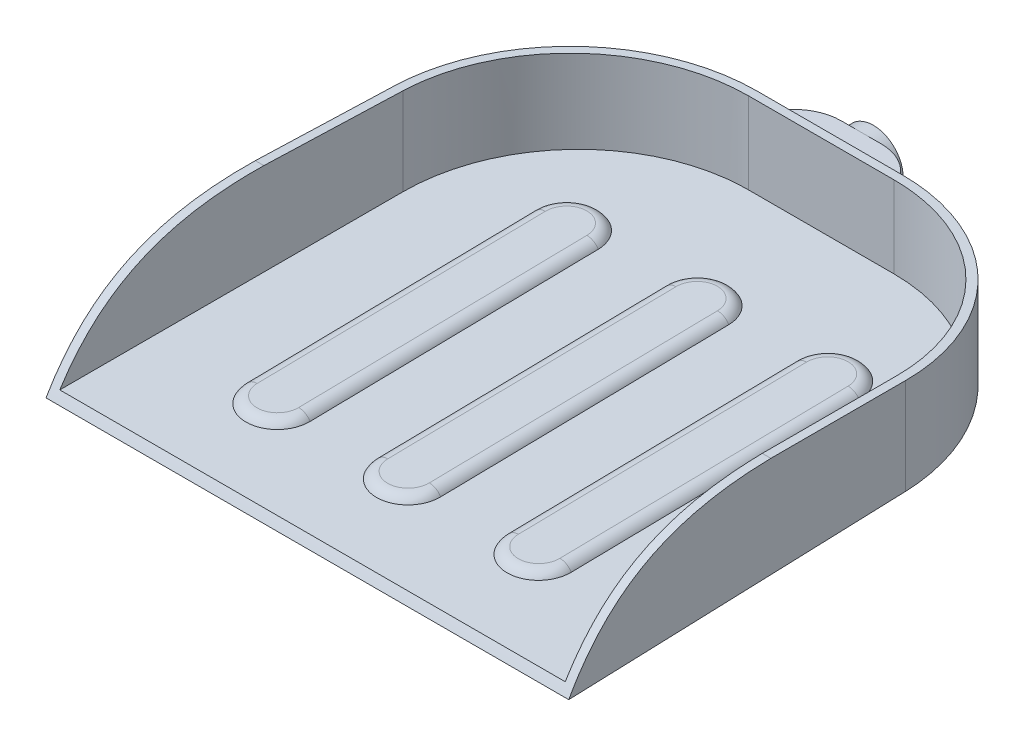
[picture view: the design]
ISO-10303-21;
HEADER;
FILE_DESCRIPTION(('STEP AP214'),'2;1');
FILE_NAME('part.step','',(''),(''),'','','');
FILE_SCHEMA(('AUTOMOTIVE_DESIGN { 1 0 10303 214 1 1 1 1 }'));
ENDSEC;
DATA;
#1=APPLICATION_CONTEXT('core data for automotive mechanical design processes');
#2=APPLICATION_PROTOCOL_DEFINITION('international standard','automotive_design',2000,#1);
#3=PRODUCT_CONTEXT('',#1,'mechanical');
#4=PRODUCT('Part','Part','',(#3));
#5=PRODUCT_RELATED_PRODUCT_CATEGORY('part','',(#4));
#6=PRODUCT_DEFINITION_FORMATION('','',#4);
#7=PRODUCT_DEFINITION_CONTEXT('part definition',#1,'design');
#8=PRODUCT_DEFINITION('design','',#6,#7);
#9=PRODUCT_DEFINITION_SHAPE('','',#8);
#10=(LENGTH_UNIT() NAMED_UNIT(*) SI_UNIT(.MILLI.,.METRE.));
#11=(NAMED_UNIT(*) PLANE_ANGLE_UNIT() SI_UNIT($,.RADIAN.));
#12=(NAMED_UNIT(*) SI_UNIT($,.STERADIAN.) SOLID_ANGLE_UNIT());
#13=UNCERTAINTY_MEASURE_WITH_UNIT(LENGTH_MEASURE(1.E-05),#10,'distance_accuracy_value','');
#14=(GEOMETRIC_REPRESENTATION_CONTEXT(3) GLOBAL_UNCERTAINTY_ASSIGNED_CONTEXT((#13)) GLOBAL_UNIT_ASSIGNED_CONTEXT((#10,
#11,#12)) REPRESENTATION_CONTEXT('',''));
#15=CARTESIAN_POINT('',(0.,0.,0.));
#16=DIRECTION('',(0.,0.,1.));
#17=DIRECTION('',(1.,0.,0.));
#18=AXIS2_PLACEMENT_3D('',#15,#16,#17);
#19=CARTESIAN_POINT('',(-152.5,31.5,-304.8));
#20=DIRECTION('',(0.,0.,-1.));
#21=DIRECTION('',(-1.,0.,0.));
#22=AXIS2_PLACEMENT_3D('',#19,#20,#21);
#23=PLANE('',#22);
#24=DIRECTION('',(1.,0.,0.));
#25=VECTOR('',#24,1.);
#26=CARTESIAN_POINT('',(-152.5,-26.1796962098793,-304.8));
#27=LINE('',#26,#25);
#28=CARTESIAN_POINT('',(-42.3455521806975,-26.1796962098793,-304.8));
#29=VERTEX_POINT('',#28);
#30=CARTESIAN_POINT('',(42.3455521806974,-26.1796962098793,-304.8));
#31=VERTEX_POINT('',#30);
#32=EDGE_CURVE('E772',#29,#31,#27,.T.);
#33=ORIENTED_EDGE('',*,*,#32,.F.);
#34=DIRECTION('',(0.,-1.,0.));
#35=VECTOR('',#34,1.);
#36=CARTESIAN_POINT('',(-42.3455521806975,31.5,-304.8));
#37=LINE('',#36,#35);
#38=CARTESIAN_POINT('',(-42.3455521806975,26.1796962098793,-304.8));
#39=VERTEX_POINT('',#38);
#40=EDGE_CURVE('E760',#29,#39,#37,.F.);
#41=ORIENTED_EDGE('',*,*,#40,.T.);
#42=DIRECTION('',(-1.,0.,0.));
#43=VECTOR('',#42,1.);
#44=CARTESIAN_POINT('',(-152.5,26.1796962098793,-304.8));
#45=LINE('',#44,#43);
#46=CARTESIAN_POINT('',(42.3455521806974,26.1796962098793,-304.8));
#47=VERTEX_POINT('',#46);
#48=EDGE_CURVE('E775',#47,#39,#45,.T.);
#49=ORIENTED_EDGE('',*,*,#48,.F.);
#50=DIRECTION('',(0.,1.,0.));
#51=VECTOR('',#50,1.);
#52=CARTESIAN_POINT('',(42.3455521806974,31.5,-304.8));
#53=LINE('',#52,#51);
#54=EDGE_CURVE('E762',#47,#31,#53,.F.);
#55=ORIENTED_EDGE('',*,*,#54,.T.);
#56=EDGE_LOOP('',(#33,#41,#49,#55));
#57=FACE_BOUND('',#56,.T.);
#58=DIRECTION('',(1.,0.,0.));
#59=VECTOR('',#58,1.);
#60=CARTESIAN_POINT('',(37.8080050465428,-13.1474560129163,-304.8));
#61=LINE('',#60,#59);
#62=CARTESIAN_POINT('',(11.4175479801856,-13.1474560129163,-304.8));
#63=VERTEX_POINT('',#62);
#64=CARTESIAN_POINT('',(37.8080050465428,-13.1474560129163,-304.8));
#65=VERTEX_POINT('',#64);
#66=EDGE_CURVE('E560',#63,#65,#61,.T.);
#67=ORIENTED_EDGE('',*,*,#66,.F.);
#68=CARTESIAN_POINT('',(0.,0.,-304.8));
#69=DIRECTION('',(0.,0.,-1.));
#70=DIRECTION('',(-1.,0.,0.));
#71=AXIS2_PLACEMENT_3D('',#68,#69,#70);
#72=CIRCLE('',#71,17.413098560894);
#73=CARTESIAN_POINT('',(11.4175479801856,13.1474560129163,-304.8));
#74=VERTEX_POINT('',#73);
#75=EDGE_CURVE('E390',#74,#63,#72,.T.);
#76=ORIENTED_EDGE('',*,*,#75,.F.);
#77=DIRECTION('',(-1.,0.,0.));
#78=VECTOR('',#77,1.);
#79=CARTESIAN_POINT('',(37.8080050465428,13.1474560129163,-304.8));
#80=LINE('',#79,#78);
#81=CARTESIAN_POINT('',(37.8080050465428,13.1474560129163,-304.8));
#82=VERTEX_POINT('',#81);
#83=EDGE_CURVE('E408',#82,#74,#80,.T.);
#84=ORIENTED_EDGE('',*,*,#83,.F.);
#85=DIRECTION('',(0.,-1.,0.));
#86=VECTOR('',#85,1.);
#87=CARTESIAN_POINT('',(37.8080050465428,13.1474560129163,-304.8));
#88=LINE('',#87,#86);
#89=CARTESIAN_POINT('',(37.8080050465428,17.413098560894,-304.8));
#90=VERTEX_POINT('',#89);
#91=EDGE_CURVE('E409',#90,#82,#88,.T.);
#92=ORIENTED_EDGE('',*,*,#91,.F.);
#93=DIRECTION('',(1.,0.,0.));
#94=VECTOR('',#93,1.);
#95=CARTESIAN_POINT('',(37.8080050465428,17.413098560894,-304.8));
#96=LINE('',#95,#94);
#97=CARTESIAN_POINT('',(-37.8080050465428,17.413098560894,-304.8));
#98=VERTEX_POINT('',#97);
#99=EDGE_CURVE('E417',#98,#90,#96,.T.);
#100=ORIENTED_EDGE('',*,*,#99,.F.);
#101=DIRECTION('',(0.,1.,0.));
#102=VECTOR('',#101,1.);
#103=CARTESIAN_POINT('',(-37.8080050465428,13.1474560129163,-304.8));
#104=LINE('',#103,#102);
#105=CARTESIAN_POINT('',(-37.8080050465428,13.1474560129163,-304.8));
#106=VERTEX_POINT('',#105);
#107=EDGE_CURVE('E406',#106,#98,#104,.T.);
#108=ORIENTED_EDGE('',*,*,#107,.F.);
#109=CARTESIAN_POINT('',(-11.4175479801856,13.1474560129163,-304.8));
#110=VERTEX_POINT('',#109);
#111=EDGE_CURVE('E396',#110,#106,#80,.T.);
#112=ORIENTED_EDGE('',*,*,#111,.F.);
#113=CARTESIAN_POINT('',(-11.4175479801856,-13.1474560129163,-304.8));
#114=VERTEX_POINT('',#113);
#115=EDGE_CURVE('E377',#114,#110,#72,.T.);
#116=ORIENTED_EDGE('',*,*,#115,.F.);
#117=CARTESIAN_POINT('',(-37.8080050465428,-13.1474560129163,-304.8));
#118=VERTEX_POINT('',#117);
#119=EDGE_CURVE('E557',#118,#114,#61,.T.);
#120=ORIENTED_EDGE('',*,*,#119,.F.);
#121=DIRECTION('',(0.,1.,0.));
#122=VECTOR('',#121,1.);
#123=CARTESIAN_POINT('',(-37.8080050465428,-13.1474560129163,-304.8));
#124=LINE('',#123,#122);
#125=CARTESIAN_POINT('',(-37.8080050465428,-17.413098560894,-304.8));
#126=VERTEX_POINT('',#125);
#127=EDGE_CURVE('E561',#126,#118,#124,.T.);
#128=ORIENTED_EDGE('',*,*,#127,.F.);
#129=DIRECTION('',(-1.,0.,0.));
#130=VECTOR('',#129,1.);
#131=CARTESIAN_POINT('',(37.8080050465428,-17.413098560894,-304.8));
#132=LINE('',#131,#130);
#133=CARTESIAN_POINT('',(37.8080050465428,-17.413098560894,-304.8));
#134=VERTEX_POINT('',#133);
#135=EDGE_CURVE('E564',#134,#126,#132,.T.);
#136=ORIENTED_EDGE('',*,*,#135,.F.);
#137=DIRECTION('',(0.,-1.,0.));
#138=VECTOR('',#137,1.);
#139=CARTESIAN_POINT('',(37.8080050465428,-13.1474560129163,-304.8));
#140=LINE('',#139,#138);
#141=EDGE_CURVE('E400',#65,#134,#140,.T.);
#142=ORIENTED_EDGE('',*,*,#141,.F.);
#143=EDGE_LOOP('',(#67,#76,#84,#92,#100,#108,#112,#116,#120,#128,#136,#142));
#144=FACE_BOUND('',#143,.T.);
#145=ADVANCED_FACE('F31',(#57,#144),#23,.T.);
#146=CARTESIAN_POINT('',(37.8080050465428,13.1474560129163,-323.088));
#147=DIRECTION('',(0.,1.,0.));
#148=DIRECTION('',(0.,0.,1.));
#149=AXIS2_PLACEMENT_3D('',#146,#147,#148);
#150=PLANE('',#149);
#151=ORIENTED_EDGE('',*,*,#111,.T.);
#152=CARTESIAN_POINT('',(-11.5881176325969,13.1474560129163,-295.148));
#153=DIRECTION('',(0.,1.,0.));
#154=DIRECTION('',(0.,0.,1.));
#155=AXIS2_PLACEMENT_3D('',#152,#153,#154);
#156=CIRCLE('',#155,27.94);
#157=CARTESIAN_POINT('',(-11.5881176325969,13.1474560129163,-323.088));
#158=VERTEX_POINT('',#157);
#159=EDGE_CURVE('E641',#106,#158,#156,.F.);
#160=ORIENTED_EDGE('',*,*,#159,.T.);
#161=DIRECTION('',(-1.,0.,0.));
#162=VECTOR('',#161,1.);
#163=CARTESIAN_POINT('',(37.8080050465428,13.1474560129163,-323.088));
#164=LINE('',#163,#162);
#165=CARTESIAN_POINT('',(-11.4175479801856,13.1474560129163,-323.088));
#166=VERTEX_POINT('',#165);
#167=EDGE_CURVE('E399',#166,#158,#164,.T.);
#168=ORIENTED_EDGE('',*,*,#167,.F.);
#169=DIRECTION('',(0.,0.,1.));
#170=VECTOR('',#169,1.);
#171=CARTESIAN_POINT('',(-11.4175479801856,13.1474560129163,-330.2));
#172=LINE('',#171,#170);
#173=EDGE_CURVE('E381',#110,#166,#172,.F.);
#174=ORIENTED_EDGE('',*,*,#173,.F.);
#175=EDGE_LOOP('',(#151,#160,#168,#174));
#176=FACE_BOUND('',#175,.T.);
#177=ADVANCED_FACE('F395',(#176),#150,.F.);
#178=CARTESIAN_POINT('',(11.5881176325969,13.1474560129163,-323.088));
#179=VERTEX_POINT('',#178);
#180=CARTESIAN_POINT('',(11.4175479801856,13.1474560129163,-323.088));
#181=VERTEX_POINT('',#180);
#182=EDGE_CURVE('E554',#179,#181,#164,.T.);
#183=ORIENTED_EDGE('',*,*,#182,.F.);
#184=CARTESIAN_POINT('',(11.5881176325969,13.1474560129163,-295.148));
#185=DIRECTION('',(0.,1.,0.));
#186=DIRECTION('',(0.,0.,1.));
#187=AXIS2_PLACEMENT_3D('',#184,#185,#186);
#188=CIRCLE('',#187,27.94);
#189=EDGE_CURVE('E11',#179,#82,#188,.F.);
#190=ORIENTED_EDGE('',*,*,#189,.T.);
#191=ORIENTED_EDGE('',*,*,#83,.T.);
#192=DIRECTION('',(0.,0.,1.));
#193=VECTOR('',#192,1.);
#194=CARTESIAN_POINT('',(11.4175479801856,13.1474560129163,-330.2));
#195=LINE('',#194,#193);
#196=EDGE_CURVE('E401',#181,#74,#195,.T.);
#197=ORIENTED_EDGE('',*,*,#196,.F.);
#198=EDGE_LOOP('',(#183,#190,#191,#197));
#199=FACE_BOUND('',#198,.T.);
#200=ADVANCED_FACE('F611',(#199),#150,.F.);
#201=CARTESIAN_POINT('',(37.8080050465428,17.413098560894,-323.088));
#202=DIRECTION('',(0.,0.,1.));
#203=DIRECTION('',(1.,0.,0.));
#204=AXIS2_PLACEMENT_3D('',#201,#202,#203);
#205=PLANE('',#204);
#206=ORIENTED_EDGE('',*,*,#167,.T.);
#207=DIRECTION('',(0.,1.,0.));
#208=VECTOR('',#207,1.);
#209=CARTESIAN_POINT('',(-11.5881176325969,17.4130985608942,-323.088));
#210=LINE('',#209,#208);
#211=CARTESIAN_POINT('',(-11.5881176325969,17.413098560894,-323.088));
#212=VERTEX_POINT('',#211);
#213=EDGE_CURVE('E642',#158,#212,#210,.T.);
#214=ORIENTED_EDGE('',*,*,#213,.T.);
#215=DIRECTION('',(1.,0.,0.));
#216=VECTOR('',#215,1.);
#217=CARTESIAN_POINT('',(37.8080050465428,17.413098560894,-323.088));
#218=LINE('',#217,#216);
#219=CARTESIAN_POINT('',(0.,17.413098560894,-323.088));
#220=VERTEX_POINT('',#219);
#221=EDGE_CURVE('E545',#212,#220,#218,.T.);
#222=ORIENTED_EDGE('',*,*,#221,.T.);
#223=CARTESIAN_POINT('',(0.,0.,-323.088));
#224=DIRECTION('',(0.,0.,1.));
#225=DIRECTION('',(1.,0.,0.));
#226=AXIS2_PLACEMENT_3D('',#223,#224,#225);
#227=CIRCLE('',#226,17.413098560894);
#228=EDGE_CURVE('E573',#166,#220,#227,.F.);
#229=ORIENTED_EDGE('',*,*,#228,.F.);
#230=EDGE_LOOP('',(#206,#214,#222,#229));
#231=FACE_BOUND('',#230,.T.);
#232=ADVANCED_FACE('F1174',(#231),#205,.F.);
#233=CARTESIAN_POINT('',(11.5881176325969,17.413098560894,-323.088));
#234=VERTEX_POINT('',#233);
#235=EDGE_CURVE('E550',#220,#234,#218,.T.);
#236=ORIENTED_EDGE('',*,*,#235,.T.);
#237=DIRECTION('',(0.,-1.,0.));
#238=VECTOR('',#237,1.);
#239=CARTESIAN_POINT('',(11.5881176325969,17.413098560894,-323.088));
#240=LINE('',#239,#238);
#241=EDGE_CURVE('E39',#234,#179,#240,.T.);
#242=ORIENTED_EDGE('',*,*,#241,.T.);
#243=ORIENTED_EDGE('',*,*,#182,.T.);
#244=EDGE_CURVE('E574',#220,#181,#227,.F.);
#245=ORIENTED_EDGE('',*,*,#244,.F.);
#246=EDGE_LOOP('',(#236,#242,#243,#245));
#247=FACE_BOUND('',#246,.T.);
#248=ADVANCED_FACE('F1167',(#247),#205,.F.);
#249=CARTESIAN_POINT('',(37.8080050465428,-13.1474560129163,-323.088));
#250=DIRECTION('',(0.,-1.,0.));
#251=DIRECTION('',(0.,0.,-1.));
#252=AXIS2_PLACEMENT_3D('',#249,#250,#251);
#253=PLANE('',#252);
#254=ORIENTED_EDGE('',*,*,#66,.T.);
#255=CARTESIAN_POINT('',(11.5881176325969,-13.1474560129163,-295.148));
#256=DIRECTION('',(0.,-1.,0.));
#257=DIRECTION('',(0.,0.,-1.));
#258=AXIS2_PLACEMENT_3D('',#255,#256,#257);
#259=CIRCLE('',#258,27.94);
#260=CARTESIAN_POINT('',(11.5881176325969,-13.1474560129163,-323.088));
#261=VERTEX_POINT('',#260);
#262=EDGE_CURVE('E649',#65,#261,#259,.F.);
#263=ORIENTED_EDGE('',*,*,#262,.T.);
#264=DIRECTION('',(1.,0.,0.));
#265=VECTOR('',#264,1.);
#266=CARTESIAN_POINT('',(37.8080050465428,-13.1474560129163,-323.088));
#267=LINE('',#266,#265);
#268=CARTESIAN_POINT('',(11.4175479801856,-13.1474560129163,-323.088));
#269=VERTEX_POINT('',#268);
#270=EDGE_CURVE('E569',#269,#261,#267,.T.);
#271=ORIENTED_EDGE('',*,*,#270,.F.);
#272=DIRECTION('',(0.,0.,1.));
#273=VECTOR('',#272,1.);
#274=CARTESIAN_POINT('',(11.4175479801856,-13.1474560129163,-330.2));
#275=LINE('',#274,#273);
#276=EDGE_CURVE('E577',#63,#269,#275,.F.);
#277=ORIENTED_EDGE('',*,*,#276,.F.);
#278=EDGE_LOOP('',(#254,#263,#271,#277));
#279=FACE_BOUND('',#278,.T.);
#280=ADVANCED_FACE('F1159',(#279),#253,.F.);
#281=CARTESIAN_POINT('',(-11.5881176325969,-13.1474560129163,-323.088));
#282=VERTEX_POINT('',#281);
#283=CARTESIAN_POINT('',(-11.4175479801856,-13.1474560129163,-323.088));
#284=VERTEX_POINT('',#283);
#285=EDGE_CURVE('E412',#282,#284,#267,.T.);
#286=ORIENTED_EDGE('',*,*,#285,.F.);
#287=CARTESIAN_POINT('',(-11.5881176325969,-13.1474560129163,-295.148));
#288=DIRECTION('',(0.,-1.,0.));
#289=DIRECTION('',(0.,0.,-1.));
#290=AXIS2_PLACEMENT_3D('',#287,#288,#289);
#291=CIRCLE('',#290,27.94);
#292=EDGE_CURVE('E658',#282,#118,#291,.F.);
#293=ORIENTED_EDGE('',*,*,#292,.T.);
#294=ORIENTED_EDGE('',*,*,#119,.T.);
#295=DIRECTION('',(0.,0.,1.));
#296=VECTOR('',#295,1.);
#297=CARTESIAN_POINT('',(-11.4175479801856,-13.1474560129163,-330.2));
#298=LINE('',#297,#296);
#299=EDGE_CURVE('E385',#284,#114,#298,.T.);
#300=ORIENTED_EDGE('',*,*,#299,.F.);
#301=EDGE_LOOP('',(#286,#293,#294,#300));
#302=FACE_BOUND('',#301,.T.);
#303=ADVANCED_FACE('F1152',(#302),#253,.F.);
#304=CARTESIAN_POINT('',(37.8080050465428,-17.413098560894,-323.088));
#305=DIRECTION('',(0.,0.,-1.));
#306=DIRECTION('',(-1.,0.,0.));
#307=AXIS2_PLACEMENT_3D('',#304,#305,#306);
#308=PLANE('',#307);
#309=DIRECTION('',(-1.,0.,0.));
#310=VECTOR('',#309,1.);
#311=CARTESIAN_POINT('',(37.8080050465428,-17.413098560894,-323.088));
#312=LINE('',#311,#310);
#313=CARTESIAN_POINT('',(0.,-17.413098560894,-323.088));
#314=VERTEX_POINT('',#313);
#315=CARTESIAN_POINT('',(-11.5881176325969,-17.413098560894,-323.088));
#316=VERTEX_POINT('',#315);
#317=EDGE_CURVE('E559',#314,#316,#312,.T.);
#318=ORIENTED_EDGE('',*,*,#317,.T.);
#319=DIRECTION('',(0.,-1.,0.));
#320=VECTOR('',#319,1.);
#321=CARTESIAN_POINT('',(-11.5881176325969,-13.1474560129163,-323.088));
#322=LINE('',#321,#320);
#323=EDGE_CURVE('E660',#316,#282,#322,.F.);
#324=ORIENTED_EDGE('',*,*,#323,.T.);
#325=ORIENTED_EDGE('',*,*,#285,.T.);
#326=CARTESIAN_POINT('',(0.,0.,-323.088));
#327=DIRECTION('',(0.,0.,-1.));
#328=DIRECTION('',(-1.,0.,0.));
#329=AXIS2_PLACEMENT_3D('',#326,#327,#328);
#330=CIRCLE('',#329,17.413098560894);
#331=EDGE_CURVE('E663',#284,#314,#330,.F.);
#332=ORIENTED_EDGE('',*,*,#331,.T.);
#333=EDGE_LOOP('',(#318,#324,#325,#332));
#334=FACE_BOUND('',#333,.T.);
#335=ADVANCED_FACE('F1143',(#334),#308,.T.);
#336=ORIENTED_EDGE('',*,*,#270,.T.);
#337=DIRECTION('',(0.,1.,0.));
#338=VECTOR('',#337,1.);
#339=CARTESIAN_POINT('',(11.5881176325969,-17.413098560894,-323.088));
#340=LINE('',#339,#338);
#341=CARTESIAN_POINT('',(11.5881176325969,-17.413098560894,-323.088));
#342=VERTEX_POINT('',#341);
#343=EDGE_CURVE('E651',#261,#342,#340,.F.);
#344=ORIENTED_EDGE('',*,*,#343,.T.);
#345=EDGE_CURVE('E570',#342,#314,#312,.T.);
#346=ORIENTED_EDGE('',*,*,#345,.T.);
#347=EDGE_CURVE('E664',#314,#269,#330,.F.);
#348=ORIENTED_EDGE('',*,*,#347,.T.);
#349=EDGE_LOOP('',(#336,#344,#346,#348));
#350=FACE_BOUND('',#349,.T.);
#351=ADVANCED_FACE('F809',(#350),#308,.T.);
#352=CARTESIAN_POINT('',(735.33971891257,-31.5,0.));
#353=CARTESIAN_POINT('',(735.33971891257,14.267169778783,-25.904790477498));
#354=CARTESIAN_POINT('',(735.33971891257,29.4048455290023,-65.6087133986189));
#355=CARTESIAN_POINT('',(735.33971891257,29.4048455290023,-120.031319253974));
#356=B_SPLINE_CURVE_WITH_KNOTS('',3,(#352,#353,#354,#355),.UNSPECIFIED.,.F.,.F.,(4,4),(0.,1.),.UNSPECIFIED.);
#357=DIRECTION('',(-1.,0.,0.));
#358=VECTOR('',#357,1.);
#359=SURFACE_OF_LINEAR_EXTRUSION('',#356,#358);
#360=DIRECTION('',(-1.,0.,0.));
#361=VECTOR('',#360,1.);
#362=CARTESIAN_POINT('',(-147.446999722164,-26.4469997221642,-2.99274954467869));
#363=LINE('',#362,#361);
#364=CARTESIAN_POINT('',(-147.446999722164,-26.4469997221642,-2.99274954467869));
#365=VERTEX_POINT('',#364);
#366=CARTESIAN_POINT('',(147.446999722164,-26.4469997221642,-2.9927495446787));
#367=VERTEX_POINT('',#366);
#368=EDGE_CURVE('E451',#365,#367,#363,.F.);
#369=ORIENTED_EDGE('',*,*,#368,.F.);
#370=CARTESIAN_POINT('',(-147.446999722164,-26.4469997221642,-2.99274954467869));
#371=CARTESIAN_POINT('',(-147.437334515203,-25.5536466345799,-3.54646888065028));
#372=CARTESIAN_POINT('',(-147.427496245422,-24.6664141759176,-4.11010297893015));
#373=CARTESIAN_POINT('',(-147.407454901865,-22.9041924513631,-5.25827078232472));
#374=CARTESIAN_POINT('',(-147.397251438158,-22.0292177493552,-5.84282682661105));
#375=CARTESIAN_POINT('',(-147.37647468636,-20.2928506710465,-7.0331261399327));
#376=CARTESIAN_POINT('',(-147.365901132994,-19.4314687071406,-7.63888460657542));
#377=CARTESIAN_POINT('',(-147.344380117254,-17.7236089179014,-8.8718227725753));
#378=CARTESIAN_POINT('',(-147.33343249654,-16.8771376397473,-9.49901154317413));
#379=CARTESIAN_POINT('',(-147.311160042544,-15.2003838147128,-10.774999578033));
#380=CARTESIAN_POINT('',(-147.299835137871,-14.3701043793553,-11.4238029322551));
#381=CARTESIAN_POINT('',(-147.276805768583,-12.7269811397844,-12.743154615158));
#382=CARTESIAN_POINT('',(-147.26510129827,-11.9141375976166,-13.4137032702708));
#383=CARTESIAN_POINT('',(-147.241347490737,-10.3095204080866,-14.7745579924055));
#384=CARTESIAN_POINT('',(-147.229299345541,-9.51768885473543,-15.4647957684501));
#385=CARTESIAN_POINT('',(-147.204825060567,-7.9537396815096,-16.8669266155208));
#386=CARTESIAN_POINT('',(-147.192399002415,-7.18161786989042,-17.5788150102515));
#387=CARTESIAN_POINT('',(-147.167170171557,-5.6581792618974,-19.0241737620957));
#388=CARTESIAN_POINT('',(-147.154367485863,-4.90685773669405,-19.7576391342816));
#389=CARTESIAN_POINT('',(-147.128387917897,-3.42604105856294,-21.2460075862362));
#390=CARTESIAN_POINT('',(-147.115211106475,-2.69654182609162,-22.0009066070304));
#391=CARTESIAN_POINT('',(-147.088487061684,-1.26031417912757,-23.5319261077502));
#392=CARTESIAN_POINT('',(-147.074939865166,-0.553583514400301,-24.3080444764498));
#393=CARTESIAN_POINT('',(-147.047480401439,0.836235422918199,-25.881196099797));
#394=CARTESIAN_POINT('',(-147.033568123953,1.51932302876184,-26.6782299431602));
#395=CARTESIAN_POINT('',(-147.002438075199,3.00137379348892,-28.4616692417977));
#396=CARTESIAN_POINT('',(-146.985137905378,3.79466649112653,-29.4527953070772));
#397=CARTESIAN_POINT('',(-146.950032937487,5.34412875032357,-31.4639575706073));
#398=CARTESIAN_POINT('',(-146.932228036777,6.10029067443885,-32.4839996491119));
#399=CARTESIAN_POINT('',(-146.896138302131,7.57426782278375,-34.5515791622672));
#400=CARTESIAN_POINT('',(-146.877853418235,8.29207903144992,-35.5991194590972));
#401=CARTESIAN_POINT('',(-146.840832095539,9.68840699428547,-37.72006961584));
#402=CARTESIAN_POINT('',(-146.822095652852,10.3669234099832,-38.7934796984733));
#403=CARTESIAN_POINT('',(-146.784202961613,11.6840043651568,-40.9643505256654));
#404=CARTESIAN_POINT('',(-146.76504676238,12.3225735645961,-42.0618084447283));
#405=CARTESIAN_POINT('',(-146.72635983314,13.5590596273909,-44.2781811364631));
#406=CARTESIAN_POINT('',(-146.706829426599,14.1570097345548,-45.3970773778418));
#407=CARTESIAN_POINT('',(-146.667412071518,15.3128331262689,-47.6552961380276));
#408=CARTESIAN_POINT('',(-146.647525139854,15.870708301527,-48.7946176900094));
#409=CARTESIAN_POINT('',(-146.607425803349,16.9467452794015,-51.0919071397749));
#410=CARTESIAN_POINT('',(-146.587213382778,17.4649051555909,-52.2498759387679));
#411=CARTESIAN_POINT('',(-146.546495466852,18.4620765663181,-54.5826037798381));
#412=CARTESIAN_POINT('',(-146.525989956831,18.9410861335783,-55.757363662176));
#413=CARTESIAN_POINT('',(-146.484720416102,19.8606939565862,-58.1216940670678));
#414=CARTESIAN_POINT('',(-146.463956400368,20.3012944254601,-59.3112637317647));
#415=CARTESIAN_POINT('',(-146.408083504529,21.4303329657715,-62.5122197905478));
#416=CARTESIAN_POINT('',(-146.372765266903,22.0849878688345,-64.5356002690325));
#417=CARTESIAN_POINT('',(-146.301609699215,23.2950238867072,-68.6121000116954));
#418=CARTESIAN_POINT('',(-146.265772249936,23.8503817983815,-70.6652261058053));
#419=CARTESIAN_POINT('',(-146.193686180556,24.8683971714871,-74.795034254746));
#420=CARTESIAN_POINT('',(-146.157437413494,25.3310203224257,-76.8717247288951));
#421=CARTESIAN_POINT('',(-146.084639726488,26.1702353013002,-81.0423014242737));
#422=CARTESIAN_POINT('',(-146.04809080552,26.5468268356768,-83.136187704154));
#423=CARTESIAN_POINT('',(-145.974666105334,27.2219880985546,-87.3426859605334));
#424=CARTESIAN_POINT('',(-145.937789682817,27.5203264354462,-89.4553347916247));
#425=CARTESIAN_POINT('',(-145.863892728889,28.0443800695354,-93.6888884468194));
#426=CARTESIAN_POINT('',(-145.82687224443,28.2701173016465,-95.8097905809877));
#427=CARTESIAN_POINT('',(-145.752732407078,28.6556741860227,-100.057259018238));
#428=CARTESIAN_POINT('',(-145.71561306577,28.8155012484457,-102.183824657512));
#429=CARTESIAN_POINT('',(-145.641319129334,29.0754416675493,-106.440121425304));
#430=CARTESIAN_POINT('',(-145.604144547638,29.1755677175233,-108.569851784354));
#431=CARTESIAN_POINT('',(-145.553364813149,29.2754525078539,-111.479020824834));
#432=CARTESIAN_POINT('',(-145.539772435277,29.2985828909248,-112.257727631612));
#433=CARTESIAN_POINT('',(-145.51258585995,29.3378978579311,-113.815245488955));
#434=CARTESIAN_POINT('',(-145.498991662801,29.354083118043,-114.594056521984));
#435=CARTESIAN_POINT('',(-145.471846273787,29.3797253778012,-116.149214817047));
#436=CARTESIAN_POINT('',(-145.458295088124,29.3892044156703,-116.925561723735));
#437=CARTESIAN_POINT('',(-145.431190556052,29.4017640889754,-118.478379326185));
#438=CARTESIAN_POINT('',(-145.417637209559,29.4048441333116,-119.254850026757));
#439=CARTESIAN_POINT('',(-145.404083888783,29.4048455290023,-120.031319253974));
#440=B_SPLINE_CURVE_WITH_KNOTS('',3,(#370,#371,#372,#373,#374,#375,#376,#377,#378,#379,#380,
#381,#382,#383,#384,#385,#386,#387,#388,#389,#390,#391,#392,#393,#394,#395,#396,#397,#398,#399,
#400,#401,#402,#403,#404,#405,#406,#407,#408,#409,#410,#411,#412,#413,#414,#415,#416,#417,#418,
#419,#420,#421,#422,#423,#424,#425,#426,#427,#428,#429,#430,#431,#432,#433,#434,#435,#436,#437,
#438,#439),.UNSPECIFIED.,.F.,.F.,(4,2,2,2,2,2,2,2,2,2,2,2,2,2,2,2,2,2,2,2,2,2,2,2,2,2,2,2,2,2,2,
2,2,2,4),(0.,3.15322192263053,6.3099174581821,9.46892397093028,12.6292846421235,15.790246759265,
18.9512563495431,22.1023876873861,25.252843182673,28.4025764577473,31.5517171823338,
34.7005457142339,37.8494629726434,41.6574401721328,45.4661973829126,49.2753526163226,
53.0845406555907,56.893283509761,60.6988706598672,64.5042781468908,68.3098701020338,
72.1156531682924,75.9212168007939,82.2990957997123,88.6784632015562,95.0601865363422,
101.441931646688,107.842339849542,114.240812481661,120.638565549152,127.03495787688,
129.372445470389,131.709705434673,134.039248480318,136.369006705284),.UNSPECIFIED.);
#441=CARTESIAN_POINT('',(-145.404083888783,29.4048455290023,-120.031319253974));
#442=VERTEX_POINT('',#441);
#443=EDGE_CURVE('E445',#365,#442,#440,.T.);
#444=ORIENTED_EDGE('',*,*,#443,.T.);
#445=DIRECTION('',(-1.,0.,0.));
#446=VECTOR('',#445,1.);
#447=CARTESIAN_POINT('',(735.33971891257,29.4048455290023,-120.031319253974));
#448=LINE('',#447,#446);
#449=CARTESIAN_POINT('',(-150.404845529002,29.4048455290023,-120.031319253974));
#450=VERTEX_POINT('',#449);
#451=EDGE_CURVE('E825',#442,#450,#448,.T.);
#452=ORIENTED_EDGE('',*,*,#451,.T.);
#453=CARTESIAN_POINT('',(-152.5,-31.4999999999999,0.));
#454=CARTESIAN_POINT('',(-152.490668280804,-30.5554742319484,-0.534613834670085));
#455=CARTESIAN_POINT('',(-152.481161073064,-29.6166135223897,-1.0792814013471));
#456=CARTESIAN_POINT('',(-152.461773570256,-27.7500046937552,-2.18999069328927));
#457=CARTESIAN_POINT('',(-152.451892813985,-26.8222723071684,-2.75605884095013));
#458=CARTESIAN_POINT('',(-152.431751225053,-24.979327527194,-3.9099696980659));
#459=CARTESIAN_POINT('',(-152.421490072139,-24.0641266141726,-4.49783075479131));
#460=CARTESIAN_POINT('',(-152.400581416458,-22.2476465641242,-5.69568683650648));
#461=CARTESIAN_POINT('',(-152.389933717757,-21.3463748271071,-6.30569308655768));
#462=CARTESIAN_POINT('',(-152.368246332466,-19.5591259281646,-7.54816255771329));
#463=CARTESIAN_POINT('',(-152.357206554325,-18.673152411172,-8.1806310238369));
#464=CARTESIAN_POINT('',(-152.334730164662,-16.9178448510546,-9.46830252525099));
#465=CARTESIAN_POINT('',(-152.323293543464,-16.0485112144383,-10.1235061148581));
#466=CARTESIAN_POINT('',(-152.300024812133,-14.3281858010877,-11.4565708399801));
#467=CARTESIAN_POINT('',(-152.288192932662,-13.4771837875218,-12.1344187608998));
#468=CARTESIAN_POINT('',(-152.264126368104,-11.7944219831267,-13.5131913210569));
#469=CARTESIAN_POINT('',(-152.251891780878,-10.9626575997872,-14.214110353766));
#470=CARTESIAN_POINT('',(-152.227018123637,-9.31959775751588,-15.6391212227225));
#471=CARTESIAN_POINT('',(-152.214379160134,-8.50829700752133,-16.3632069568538));
#472=CARTESIAN_POINT('',(-152.188696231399,-6.90733200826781,-17.8345809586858));
#473=CARTESIAN_POINT('',(-152.175652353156,-6.11766317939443,-18.5818642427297));
#474=CARTESIAN_POINT('',(-152.149160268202,-4.5610620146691,-20.099594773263));
#475=CARTESIAN_POINT('',(-152.135712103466,-3.79412733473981,-20.8700396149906));
#476=CARTESIAN_POINT('',(-152.108413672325,-2.28403162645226,-22.4339656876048));
#477=CARTESIAN_POINT('',(-152.094563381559,-1.54087204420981,-23.2274483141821));
#478=CARTESIAN_POINT('',(-152.06349561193,0.0751252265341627,-25.0073196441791));
#479=CARTESIAN_POINT('',(-152.046185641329,0.942138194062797,-25.999007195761));
#480=CARTESIAN_POINT('',(-152.010998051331,2.6379725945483,-28.0149028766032));
#481=CARTESIAN_POINT('',(-151.993120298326,3.46678492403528,-29.039118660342));
#482=CARTESIAN_POINT('',(-151.956820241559,5.08451476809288,-31.1187475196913));
#483=CARTESIAN_POINT('',(-151.938397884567,5.87342836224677,-32.1741636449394));
#484=CARTESIAN_POINT('',(-151.90103615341,7.40996384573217,-34.3146157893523));
#485=CARTESIAN_POINT('',(-151.882096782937,8.1575860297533,-35.399651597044));
#486=CARTESIAN_POINT('',(-151.843732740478,9.61047070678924,-37.5975261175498));
#487=CARTESIAN_POINT('',(-151.824308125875,10.3157381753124,-38.7103615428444));
#488=CARTESIAN_POINT('',(-151.785045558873,11.6819176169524,-40.9597124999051));
#489=CARTESIAN_POINT('',(-151.765208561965,12.3429197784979,-42.0961732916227));
#490=CARTESIAN_POINT('',(-151.725116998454,13.621872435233,-44.3930174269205));
#491=CARTESIAN_POINT('',(-151.70486244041,14.2398238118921,-45.5534002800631));
#492=CARTESIAN_POINT('',(-151.663970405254,15.4327622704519,-47.8961034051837));
#493=CARTESIAN_POINT('',(-151.643332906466,16.0077469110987,-49.0784249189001));
#494=CARTESIAN_POINT('',(-151.601711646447,17.1151048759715,-51.4629053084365));
#495=CARTESIAN_POINT('',(-151.580727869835,17.6474763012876,-52.665065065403));
#496=CARTESIAN_POINT('',(-151.538453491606,18.6701937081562,-55.0869625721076));
#497=CARTESIAN_POINT('',(-151.517162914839,19.160543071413,-56.3066988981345));
#498=CARTESIAN_POINT('',(-151.462582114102,20.357282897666,-59.4336308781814));
#499=CARTESIAN_POINT('',(-151.429099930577,21.0350879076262,-61.3518238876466));
#500=CARTESIAN_POINT('',(-151.361598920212,22.2968934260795,-65.218954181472));
#501=CARTESIAN_POINT('',(-151.327580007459,22.8808787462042,-67.1678963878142));
#502=CARTESIAN_POINT('',(-151.259108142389,23.9604734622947,-71.0906469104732));
#503=CARTESIAN_POINT('',(-151.224655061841,24.4560560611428,-73.0644625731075));
#504=CARTESIAN_POINT('',(-151.155420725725,25.3645012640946,-77.0308950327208));
#505=CARTESIAN_POINT('',(-151.120639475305,25.7773651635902,-79.0235115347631));
#506=CARTESIAN_POINT('',(-151.050688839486,26.5280057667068,-83.0309807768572));
#507=CARTESIAN_POINT('',(-151.015518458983,26.8654761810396,-85.0458905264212));
#508=CARTESIAN_POINT('',(-150.945002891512,27.4693377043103,-89.0857246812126));
#509=CARTESIAN_POINT('',(-150.909657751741,27.7357470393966,-91.1106463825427));
#510=CARTESIAN_POINT('',(-150.838840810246,28.2035942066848,-95.1677462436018));
#511=CARTESIAN_POINT('',(-150.803369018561,28.405037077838,-97.1999238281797));
#512=CARTESIAN_POINT('',(-150.732345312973,28.7486729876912,-101.268869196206));
#513=CARTESIAN_POINT('',(-150.696793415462,28.8908772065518,-103.305636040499));
#514=CARTESIAN_POINT('',(-150.646948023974,29.0523884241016,-106.161276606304));
#515=CARTESIAN_POINT('',(-150.632675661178,29.0942903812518,-106.978939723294));
#516=CARTESIAN_POINT('',(-150.604126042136,29.1697537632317,-108.614546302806));
#517=CARTESIAN_POINT('',(-150.589848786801,29.2033163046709,-109.432489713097));
#518=CARTESIAN_POINT('',(-150.561290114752,29.2624249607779,-111.068614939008));
#519=CARTESIAN_POINT('',(-150.547008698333,29.2879715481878,-111.886796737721));
#520=CARTESIAN_POINT('',(-150.518521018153,29.3312388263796,-113.518854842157));
#521=CARTESIAN_POINT('',(-150.504314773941,29.3490018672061,-114.332730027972));
#522=CARTESIAN_POINT('',(-150.475899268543,29.3772003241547,-115.960653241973));
#523=CARTESIAN_POINT('',(-150.461690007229,29.3876353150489,-116.774701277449));
#524=CARTESIAN_POINT('',(-150.433268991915,29.4014573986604,-118.402940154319));
#525=CARTESIAN_POINT('',(-150.419057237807,29.4048437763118,-119.217131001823));
#526=CARTESIAN_POINT('',(-150.404845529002,29.4048455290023,-120.031319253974));
#527=B_SPLINE_CURVE_WITH_KNOTS('',3,(#453,#454,#455,#456,#457,#458,#459,#460,#461,#462,#463,
#464,#465,#466,#467,#468,#469,#470,#471,#472,#473,#474,#475,#476,#477,#478,#479,#480,#481,#482,
#483,#484,#485,#486,#487,#488,#489,#490,#491,#492,#493,#494,#495,#496,#497,#498,#499,#500,#501,
#502,#503,#504,#505,#506,#507,#508,#509,#510,#511,#512,#513,#514,#515,#516,#517,#518,#519,#520,
#521,#522,#523,#524,#525,#526),.UNSPECIFIED.,.F.,.F.,(4,2,2,2,2,2,2,2,2,2,2,2,2,2,2,2,2,2,2,2,2,
2,2,2,2,2,2,2,2,2,2,2,2,2,2,2,4),(0.,3.2560836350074,6.51632786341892,9.77938214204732,
13.0441141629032,16.3096135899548,19.5751926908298,22.8388982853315,26.1018165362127,
29.3638822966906,32.625252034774,35.886284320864,39.147514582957,43.0986440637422,
47.0507103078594,51.0031641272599,54.955589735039,58.9075501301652,62.8511968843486,
66.7947628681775,70.7385527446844,74.6825182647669,78.6261660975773,84.7275183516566,
90.829857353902,96.9340429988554,103.038133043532,109.166587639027,115.293468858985,
121.419874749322,127.545123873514,130.00167655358,132.457900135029,134.913978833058,
137.356522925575,139.799208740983,142.242142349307),.UNSPECIFIED.);
#528=CARTESIAN_POINT('',(-152.5,-31.5,0.));
#529=VERTEX_POINT('',#528);
#530=EDGE_CURVE('E789',#529,#450,#527,.T.);
#531=ORIENTED_EDGE('',*,*,#530,.F.);
#532=DIRECTION('',(1.,0.,0.));
#533=VECTOR('',#532,1.);
#534=CARTESIAN_POINT('',(-152.5,-31.5,0.));
#535=LINE('',#534,#533);
#536=CARTESIAN_POINT('',(152.5,-31.5,0.));
#537=VERTEX_POINT('',#536);
#538=EDGE_CURVE('E776',#529,#537,#535,.T.);
#539=ORIENTED_EDGE('',*,*,#538,.T.);
#540=CARTESIAN_POINT('',(150.404845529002,29.4048455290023,-120.031319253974));
#541=CARTESIAN_POINT('',(150.431344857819,29.4048240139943,-118.513173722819));
#542=CARTESIAN_POINT('',(150.457844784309,29.393064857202,-116.994993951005));
#543=CARTESIAN_POINT('',(150.510910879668,29.34411134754,-113.954839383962));
#544=CARTESIAN_POINT('',(150.537477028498,29.3068465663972,-112.432865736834));
#545=CARTESIAN_POINT('',(150.590646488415,29.2047992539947,-109.386789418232));
#546=CARTESIAN_POINT('',(150.617249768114,29.1399620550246,-107.862688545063));
#547=CARTESIAN_POINT('',(150.670463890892,28.9805842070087,-104.814053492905));
#548=CARTESIAN_POINT('',(150.697074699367,28.8860053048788,-103.289521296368));
#549=CARTESIAN_POINT('',(150.750274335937,28.6648983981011,-100.241716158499));
#550=CARTESIAN_POINT('',(150.776863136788,28.5383487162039,-98.718444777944));
#551=CARTESIAN_POINT('',(150.829989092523,28.2509870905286,-95.6748608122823));
#552=CARTESIAN_POINT('',(150.856526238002,28.0901694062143,-94.1545487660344));
#553=CARTESIAN_POINT('',(150.909992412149,27.7286989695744,-91.0914737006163));
#554=CARTESIAN_POINT('',(150.936920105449,27.5273941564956,-89.5487871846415));
#555=CARTESIAN_POINT('',(150.990660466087,27.084260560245,-86.4700039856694));
#556=CARTESIAN_POINT('',(151.017473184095,26.8424520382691,-84.9339043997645));
#557=CARTESIAN_POINT('',(151.070952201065,26.3156927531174,-81.8700935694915));
#558=CARTESIAN_POINT('',(151.097618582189,26.0307694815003,-80.3423776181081));
#559=CARTESIAN_POINT('',(151.150773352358,25.4151202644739,-77.2971428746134));
#560=CARTESIAN_POINT('',(151.177261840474,25.0844224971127,-75.7796184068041));
#561=CARTESIAN_POINT('',(151.230029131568,24.3745333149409,-72.7565823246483));
#562=CARTESIAN_POINT('',(151.256308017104,23.9953621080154,-71.2510659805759));
#563=CARTESIAN_POINT('',(151.308624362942,23.1858177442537,-68.2538645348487));
#564=CARTESIAN_POINT('',(151.334661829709,22.7554459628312,-66.7621790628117));
#565=CARTESIAN_POINT('',(151.386284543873,21.8439527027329,-63.8047157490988));
#566=CARTESIAN_POINT('',(151.411871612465,21.3631706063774,-62.3388335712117));
#567=CARTESIAN_POINT('',(151.46271501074,20.3464057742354,-59.4260172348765));
#568=CARTESIAN_POINT('',(151.487971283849,19.8104137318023,-57.9790863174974));
#569=CARTESIAN_POINT('',(151.538093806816,18.6815037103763,-55.1075688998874));
#570=CARTESIAN_POINT('',(151.562960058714,18.0885860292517,-53.6829822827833));
#571=CARTESIAN_POINT('',(151.612245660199,16.8444533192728,-50.8594120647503));
#572=CARTESIAN_POINT('',(151.636664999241,16.1932369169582,-49.460429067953));
#573=CARTESIAN_POINT('',(151.684827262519,14.836478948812,-46.7012148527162));
#574=CARTESIAN_POINT('',(151.708573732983,14.1313510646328,-45.340780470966));
#575=CARTESIAN_POINT('',(151.755511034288,12.6625448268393,-42.651744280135));
#576=CARTESIAN_POINT('',(151.778701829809,11.8988627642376,-41.3231444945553));
#577=CARTESIAN_POINT('',(151.824469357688,10.3134419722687,-38.7011245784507));
#578=CARTESIAN_POINT('',(151.847046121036,9.49170618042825,-37.4077026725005));
#579=CARTESIAN_POINT('',(151.891534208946,7.79122234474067,-34.8589818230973));
#580=CARTESIAN_POINT('',(151.913445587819,6.9124789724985,-33.6036797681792));
#581=CARTESIAN_POINT('',(151.949426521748,5.39952589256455,-31.5423334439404));
#582=CARTESIAN_POINT('',(151.963692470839,4.78058155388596,-30.7250377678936));
#583=CARTESIAN_POINT('',(151.991895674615,3.51851186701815,-29.1092773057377));
#584=CARTESIAN_POINT('',(152.005832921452,2.8753859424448,-28.3108129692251));
#585=CARTESIAN_POINT('',(152.033368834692,1.56566828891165,-26.7332815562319));
#586=CARTESIAN_POINT('',(152.046967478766,0.899075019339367,-25.9542157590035));
#587=CARTESIAN_POINT('',(152.073817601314,-0.456747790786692,-24.4159732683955));
#588=CARTESIAN_POINT('',(152.087069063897,-1.14597836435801,-23.656797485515));
#589=CARTESIAN_POINT('',(152.113217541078,-2.54614869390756,-22.1587522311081));
#590=CARTESIAN_POINT('',(152.12611456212,-3.25708805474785,-21.4198823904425));
#591=CARTESIAN_POINT('',(152.151550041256,-4.69974230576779,-19.9626847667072));
#592=CARTESIAN_POINT('',(152.164088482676,-5.43145815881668,-19.2443579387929));
#593=CARTESIAN_POINT('',(152.201239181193,-7.66098686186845,-17.1159958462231));
#594=CARTESIAN_POINT('',(152.225306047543,-9.18884729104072,-15.7372059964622));
#595=CARTESIAN_POINT('',(152.271977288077,-12.3157189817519,-13.0634124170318));
#596=CARTESIAN_POINT('',(152.294581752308,-13.9147258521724,-11.7684035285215));
#597=CARTESIAN_POINT('',(152.338350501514,-17.1754730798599,-9.2608935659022));
#598=CARTESIAN_POINT('',(152.359515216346,-18.837194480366,-8.04836786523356));
#599=CARTESIAN_POINT('',(152.387164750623,-21.1191012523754,-6.46432710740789));
#600=CARTESIAN_POINT('',(152.394261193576,-21.7152350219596,-6.05777216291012));
#601=CARTESIAN_POINT('',(152.408284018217,-22.9138726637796,-5.25440507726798));
#602=CARTESIAN_POINT('',(152.415210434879,-23.5163751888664,-4.85759093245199));
#603=CARTESIAN_POINT('',(152.428896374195,-24.727487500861,-4.07352399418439));
#604=CARTESIAN_POINT('',(152.43565591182,-25.3360967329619,-3.68627034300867));
#605=CARTESIAN_POINT('',(152.448979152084,-26.556218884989,-2.9229824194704));
#606=CARTESIAN_POINT('',(152.455543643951,-27.167703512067,-2.54690293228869));
#607=CARTESIAN_POINT('',(152.468513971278,-28.3962419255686,-1.80383337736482));
#608=CARTESIAN_POINT('',(152.474919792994,-29.013296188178,-1.43684409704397));
#609=CARTESIAN_POINT('',(152.487576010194,-30.2527382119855,-0.711769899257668));
#610=CARTESIAN_POINT('',(152.493826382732,-30.8751267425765,-0.353686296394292));
#611=CARTESIAN_POINT('',(152.5,-31.5,0.));
#612=B_SPLINE_CURVE_WITH_KNOTS('',3,(#540,#541,#542,#543,#544,#545,#546,#547,#548,#549,#550,
#551,#552,#553,#554,#555,#556,#557,#558,#559,#560,#561,#562,#563,#564,#565,#566,#567,#568,#569,
#570,#571,#572,#573,#574,#575,#576,#577,#578,#579,#580,#581,#582,#583,#584,#585,#586,#587,#588,
#589,#590,#591,#592,#593,#594,#595,#596,#597,#598,#599,#600,#601,#602,#603,#604,#605,#606,#607,
#608,#609,#610,#611),.UNSPECIFIED.,.F.,.F.,(4,2,2,2,2,2,2,2,2,2,2,2,2,2,2,2,2,2,2,2,2,2,2,2,2,2,
2,2,2,2,2,2,2,2,2,4),(0.,4.55513608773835,9.12290121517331,13.6997653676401,18.2825404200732,
22.8684311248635,27.4550906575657,32.1225798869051,36.7877412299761,41.4499403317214,
46.1092821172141,50.7666877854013,55.4239683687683,60.0516944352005,64.6802018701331,
69.3086850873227,73.9372773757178,78.5333604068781,83.1297348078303,87.7258767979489,
92.3216426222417,95.397164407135,98.4727595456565,101.548556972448,104.624494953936,
107.700376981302,110.776401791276,116.947444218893,123.118106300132,129.286917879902,
131.451674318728,133.61598167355,135.780094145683,137.933736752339,140.087565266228,
142.241709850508),.UNSPECIFIED.);
#613=CARTESIAN_POINT('',(150.404845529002,29.4048455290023,-120.031319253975));
#614=VERTEX_POINT('',#613);
#615=EDGE_CURVE('E795',#614,#537,#612,.T.);
#616=ORIENTED_EDGE('',*,*,#615,.F.);
#617=CARTESIAN_POINT('',(145.404083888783,29.4048455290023,-120.031319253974));
#618=VERTEX_POINT('',#617);
#619=EDGE_CURVE('E820',#614,#618,#448,.T.);
#620=ORIENTED_EDGE('',*,*,#619,.T.);
#621=CARTESIAN_POINT('',(147.460544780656,-27.7135913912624,-2.21675366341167));
#622=CARTESIAN_POINT('',(147.449112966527,-26.6321186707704,-2.87168185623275));
#623=CARTESIAN_POINT('',(147.437433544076,-25.5591843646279,-3.54079552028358));
#624=CARTESIAN_POINT('',(147.413544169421,-23.4301322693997,-4.90941687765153));
#625=CARTESIAN_POINT('',(147.401333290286,-22.3740486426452,-5.6089776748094));
#626=CARTESIAN_POINT('',(147.376372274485,-20.2811349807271,-7.03899331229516));
#627=CARTESIAN_POINT('',(147.363621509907,-19.2443295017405,-7.76948412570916));
#628=CARTESIAN_POINT('',(147.337574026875,-17.1923694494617,-9.2617434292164));
#629=CARTESIAN_POINT('',(147.324276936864,-16.1772303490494,-10.023533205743));
#630=CARTESIAN_POINT('',(147.297131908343,-14.1709157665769,-11.5786708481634));
#631=CARTESIAN_POINT('',(147.283283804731,-13.1797476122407,-12.3720281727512));
#632=CARTESIAN_POINT('',(147.255034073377,-11.2235990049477,-13.9904541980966));
#633=CARTESIAN_POINT('',(147.240632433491,-10.2586191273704,-14.8155235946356));
#634=CARTESIAN_POINT('',(147.211394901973,-8.36470427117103,-16.4905406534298));
#635=CARTESIAN_POINT('',(147.196563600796,-7.43553677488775,-17.3402253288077));
#636=CARTESIAN_POINT('',(147.166360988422,-5.60713393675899,-19.0705318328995));
#637=CARTESIAN_POINT('',(147.15098988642,-4.70788725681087,-19.9511416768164));
#638=CARTESIAN_POINT('',(147.119713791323,-2.94115386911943,-21.7429479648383));
#639=CARTESIAN_POINT('',(147.103809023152,-2.07365409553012,-22.6541315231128));
#640=CARTESIAN_POINT('',(147.071474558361,-0.372066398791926,-24.506571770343));
#641=CARTESIAN_POINT('',(147.05504505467,0.462033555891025,-25.4478174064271));
#642=CARTESIAN_POINT('',(147.021673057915,2.0953578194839,-27.3596978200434));
#643=CARTESIAN_POINT('',(147.00473069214,2.89459066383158,-28.3303253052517));
#644=CARTESIAN_POINT('',(146.970348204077,4.45691014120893,-30.3000967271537));
#645=CARTESIAN_POINT('',(146.952908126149,5.21999997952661,-31.2992381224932));
#646=CARTESIAN_POINT('',(146.916110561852,6.7695239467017,-33.4073691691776));
#647=CARTESIAN_POINT('',(146.896712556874,7.5528019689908,-34.5186801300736));
#648=CARTESIAN_POINT('',(146.857384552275,9.07475656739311,-36.7717800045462));
#649=CARTESIAN_POINT('',(146.837454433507,9.81342303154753,-37.9135757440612));
#650=CARTESIAN_POINT('',(146.797098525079,11.2452661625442,-40.2255641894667));
#651=CARTESIAN_POINT('',(146.776672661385,11.9384359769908,-41.3957611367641));
#652=CARTESIAN_POINT('',(146.735365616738,13.2787684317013,-43.7622401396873));
#653=CARTESIAN_POINT('',(146.714484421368,13.9259296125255,-44.9585230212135));
#654=CARTESIAN_POINT('',(146.672310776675,15.1740924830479,-47.3746495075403));
#655=CARTESIAN_POINT('',(146.651018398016,15.7751020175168,-48.5944890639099));
#656=CARTESIAN_POINT('',(146.608090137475,16.9306120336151,-51.0538474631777));
#657=CARTESIAN_POINT('',(146.586454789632,17.4851777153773,-52.2933357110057));
#658=CARTESIAN_POINT('',(146.542853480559,18.5493928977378,-54.7912530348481));
#659=CARTESIAN_POINT('',(146.520887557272,19.0590475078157,-56.0496799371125));
#660=CARTESIAN_POINT('',(146.476660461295,20.0345347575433,-58.5834485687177));
#661=CARTESIAN_POINT('',(146.4543992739,20.5003652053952,-59.8587911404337));
#662=CARTESIAN_POINT('',(146.409617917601,21.3894652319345,-62.4243133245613));
#663=CARTESIAN_POINT('',(146.387097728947,21.8127315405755,-63.7144940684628));
#664=CARTESIAN_POINT('',(146.341835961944,22.6181016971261,-66.3075389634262));
#665=CARTESIAN_POINT('',(146.319094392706,23.0002072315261,-67.6104025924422));
#666=CARTESIAN_POINT('',(146.264453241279,23.867171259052,-70.7407920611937));
#667=CARTESIAN_POINT('',(146.232463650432,24.33347116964,-72.5734744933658));
#668=CARTESIAN_POINT('',(146.168188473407,25.1941441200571,-76.2557969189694));
#669=CARTESIAN_POINT('',(146.13590284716,25.588507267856,-78.1054392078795));
#670=CARTESIAN_POINT('',(146.071106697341,26.3101266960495,-81.8176081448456));
#671=CARTESIAN_POINT('',(146.038596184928,26.637386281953,-83.6801341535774));
#672=CARTESIAN_POINT('',(145.973405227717,27.2297363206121,-87.4149215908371));
#673=CARTESIAN_POINT('',(145.940724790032,27.4948293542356,-89.2871826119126));
#674=CARTESIAN_POINT('',(145.886035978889,27.8897168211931,-92.4203025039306));
#675=CARTESIAN_POINT('',(145.864061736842,28.0353020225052,-93.6792059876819));
#676=CARTESIAN_POINT('',(145.820068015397,28.3021199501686,-96.1996046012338));
#677=CARTESIAN_POINT('',(145.798048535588,28.4233524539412,-97.4610997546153));
#678=CARTESIAN_POINT('',(145.753974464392,28.6428229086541,-99.9861016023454));
#679=CARTESIAN_POINT('',(145.731919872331,28.741060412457,-101.249608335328));
#680=CARTESIAN_POINT('',(145.687784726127,28.9158440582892,-103.778109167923));
#681=CARTESIAN_POINT('',(145.665704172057,28.9923902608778,-105.043103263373));
#682=CARTESIAN_POINT('',(145.621524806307,29.125041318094,-107.574137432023));
#683=CARTESIAN_POINT('',(145.599425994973,29.1811465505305,-108.840177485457));
#684=CARTESIAN_POINT('',(145.566269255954,29.2508664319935,-110.739725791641));
#685=CARTESIAN_POINT('',(145.555215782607,29.2716998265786,-111.372978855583));
#686=CARTESIAN_POINT('',(145.533106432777,29.3086976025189,-112.639622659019));
#687=CARTESIAN_POINT('',(145.522050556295,29.3248619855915,-113.273013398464));
#688=CARTESIAN_POINT('',(145.502766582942,29.3491046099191,-114.377791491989));
#689=CARTESIAN_POINT('',(145.494538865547,29.3581935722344,-114.849157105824));
#690=CARTESIAN_POINT('',(145.478082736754,29.3739199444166,-115.791928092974));
#691=CARTESIAN_POINT('',(145.469854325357,29.3805573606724,-116.263333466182));
#692=CARTESIAN_POINT('',(145.453397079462,29.3914363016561,-117.206168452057));
#693=CARTESIAN_POINT('',(145.445168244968,29.3956778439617,-117.67759806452));
#694=CARTESIAN_POINT('',(145.432824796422,29.4002825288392,-118.384753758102));
#695=CARTESIAN_POINT('',(145.428710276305,29.4015244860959,-118.62047445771));
#696=CARTESIAN_POINT('',(145.420481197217,29.4034313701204,-119.091918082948));
#697=CARTESIAN_POINT('',(145.416366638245,29.4040962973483,-119.327641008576));
#698=CARTESIAN_POINT('',(145.410194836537,29.4046591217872,-119.681223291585));
#699=CARTESIAN_POINT('',(145.408137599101,29.4047743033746,-119.799082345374));
#700=CARTESIAN_POINT('',(145.404023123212,29.4048721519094,-120.034800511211));
#701=CARTESIAN_POINT('',(145.401965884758,29.4048548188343,-120.152659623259));
#702=CARTESIAN_POINT('',(145.395794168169,29.4048269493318,-120.50623702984));
#703=CARTESIAN_POINT('',(145.39167969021,29.4048405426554,-120.741955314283));
#704=CARTESIAN_POINT('',(145.383450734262,29.404850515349,-121.21339188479));
#705=CARTESIAN_POINT('',(145.379336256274,29.4048468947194,-121.449110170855));
#706=CARTESIAN_POINT('',(145.37110730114,29.4048441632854,-121.92054669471));
#707=CARTESIAN_POINT('',(145.366992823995,29.40484505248,-122.156264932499));
#708=CARTESIAN_POINT('',(145.354649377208,29.4048464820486,-122.863420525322));
#709=CARTESIAN_POINT('',(145.346420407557,29.4048457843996,-123.334857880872));
#710=CARTESIAN_POINT('',(145.329962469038,29.4048452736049,-124.277732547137));
#711=CARTESIAN_POINT('',(145.32173350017,29.4048454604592,-124.749169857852));
#712=CARTESIAN_POINT('',(145.305275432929,29.4048455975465,-125.69205189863));
#713=CARTESIAN_POINT('',(145.297046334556,29.4048455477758,-126.163496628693));
#714=CARTESIAN_POINT('',(145.280588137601,29.4048455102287,-127.106386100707));
#715=CARTESIAN_POINT('',(145.272359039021,29.4048455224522,-127.577830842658));
#716=CARTESIAN_POINT('',(145.247671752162,29.4048455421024,-128.992164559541));
#717=CARTESIAN_POINT('',(145.231213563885,29.404845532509,-129.935053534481));
#718=CARTESIAN_POINT('',(145.198297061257,29.4048455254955,-131.820838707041));
#719=CARTESIAN_POINT('',(145.181838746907,29.4048455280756,-132.763734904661));
#720=CARTESIAN_POINT('',(145.148922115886,29.404845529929,-134.649527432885));
#721=CARTESIAN_POINT('',(145.132463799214,29.4048455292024,-135.592423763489));
#722=CARTESIAN_POINT('',(145.105177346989,29.4048455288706,-137.1556635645));
#723=CARTESIAN_POINT('',(145.094349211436,29.4048455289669,-137.776007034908));
#724=CARTESIAN_POINT('',(145.072692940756,29.4048455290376,-139.016693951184));
#725=CARTESIAN_POINT('',(145.061864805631,29.4048455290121,-139.637037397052));
#726=CARTESIAN_POINT('',(145.040208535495,29.4048455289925,-140.877724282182));
#727=CARTESIAN_POINT('',(145.029380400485,29.4048455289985,-141.498067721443));
#728=CARTESIAN_POINT('',(144.986068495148,29.4048455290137,-143.97940511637));
#729=CARTESIAN_POINT('',(144.953584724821,29.4048455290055,-145.840399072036));
#730=CARTESIAN_POINT('',(144.888618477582,29.404845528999,-149.562312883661));
#731=CARTESIAN_POINT('',(144.85613600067,29.4048455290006,-151.423232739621));
#732=CARTESIAN_POINT('',(144.791172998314,29.4048455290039,-155.144960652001));
#733=CARTESIAN_POINT('',(144.75869247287,29.4048455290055,-157.005768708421));
#734=CARTESIAN_POINT('',(144.726211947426,29.4048455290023,-158.866576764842));
#735=B_SPLINE_CURVE_WITH_KNOTS('',3,(#621,#622,#623,#624,#625,#626,#627,#628,#629,#630,#631,
#632,#633,#634,#635,#636,#637,#638,#639,#640,#641,#642,#643,#644,#645,#646,#647,#648,#649,#650,
#651,#652,#653,#654,#655,#656,#657,#658,#659,#660,#661,#662,#663,#664,#665,#666,#667,#668,#669,
#670,#671,#672,#673,#674,#675,#676,#677,#678,#679,#680,#681,#682,#683,#684,#685,#686,#687,#688,
#689,#690,#691,#692,#693,#694,#695,#696,#697,#698,#699,#700,#701,#702,#703,#704,#705,#706,#707,
#708,#709,#710,#711,#712,#713,#714,#715,#716,#717,#718,#719,#720,#721,#722,#723,#724,#725,#726,
#727,#728,#729,#730,#731,#732,#733,#734),.UNSPECIFIED.,.F.,.F.,(4,2,2,2,2,2,2,2,2,2,2,2,2,2,2,2,
2,2,2,2,2,2,2,2,2,2,2,2,2,2,2,2,2,2,2,2,2,2,2,2,2,2,2,2,2,2,2,2,2,2,2,2,2,2,2,2,4),(0.,
3.79308702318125,7.59307788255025,11.3976167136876,15.204787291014,19.0131073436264,
22.8215110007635,26.598338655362,30.373718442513,34.1475265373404,37.919962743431,
41.6914702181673,45.4626425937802,49.5407932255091,53.6198647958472,57.6995493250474,
61.7793632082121,65.8584820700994,69.9317749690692,74.0046038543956,78.0776363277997,
82.1509814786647,86.2241596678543,91.8965429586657,97.5697056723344,103.242588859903,
108.915236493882,112.71746665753,116.51973157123,120.322070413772,124.124398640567,
127.926656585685,129.82771908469,131.728780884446,133.143350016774,134.557915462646,
135.972470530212,136.679749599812,137.387028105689,137.740659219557,138.094290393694,
138.801552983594,139.508815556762,140.216077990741,141.630605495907,143.045132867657,
144.459682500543,145.874232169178,148.703329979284,151.532449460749,154.36156934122,
156.222883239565,158.084197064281,159.945510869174,165.529343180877,171.1129531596,
176.696227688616),.UNSPECIFIED.);
#736=EDGE_CURVE('E438',#618,#367,#735,.F.);
#737=ORIENTED_EDGE('',*,*,#736,.T.);
#738=EDGE_LOOP('',(#369,#444,#452,#531,#539,#616,#620,#737));
#739=FACE_BOUND('',#738,.T.);
#740=ADVANCED_FACE('F804',(#739),#359,.T.);
#741=CARTESIAN_POINT('',(-152.5,-31.5,0.));
#742=DIRECTION('',(-0.999847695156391,0.,-0.0174524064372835));
#743=DIRECTION('',(-0.0174524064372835,0.,0.999847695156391));
#744=AXIS2_PLACEMENT_3D('',#741,#742,#743);
#745=PLANE('',#744);
#746=DIRECTION('',(-0.0174497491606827,0.0174497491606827,0.999695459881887));
#747=VECTOR('',#746,1.);
#748=CARTESIAN_POINT('',(-152.5,31.5,0.));
#749=LINE('',#748,#747);
#750=CARTESIAN_POINT('',(-149.009304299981,28.0093042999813,-199.981822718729));
#751=VERTEX_POINT('',#750);
#752=EDGE_CURVE('E771',#751,#450,#749,.T.);
#753=ORIENTED_EDGE('',*,*,#752,.F.);
#754=DIRECTION('',(0.,-1.,0.));
#755=VECTOR('',#754,1.);
#756=CARTESIAN_POINT('',(-149.009304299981,-31.5,-199.981822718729));
#757=LINE('',#756,#755);
#758=CARTESIAN_POINT('',(-149.009304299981,-28.0093042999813,-199.981822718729));
#759=VERTEX_POINT('',#758);
#760=EDGE_CURVE('E768',#751,#759,#757,.T.);
#761=ORIENTED_EDGE('',*,*,#760,.T.);
#762=DIRECTION('',(-0.0174497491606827,-0.0174497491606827,0.999695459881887));
#763=VECTOR('',#762,1.);
#764=CARTESIAN_POINT('',(-152.5,-31.5,0.));
#765=LINE('',#764,#763);
#766=EDGE_CURVE('E779',#759,#529,#765,.T.);
#767=ORIENTED_EDGE('',*,*,#766,.T.);
#768=ORIENTED_EDGE('',*,*,#530,.T.);
#769=EDGE_LOOP('',(#753,#761,#767,#768));
#770=FACE_BOUND('',#769,.T.);
#771=ADVANCED_FACE('F801',(#770),#745,.T.);
#772=CARTESIAN_POINT('',(-152.5,31.5,0.));
#773=DIRECTION('',(0.,0.999847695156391,-0.0174524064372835));
#774=DIRECTION('',(0.,0.0174524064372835,0.999847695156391));
#775=AXIS2_PLACEMENT_3D('',#772,#773,#774);
#776=PLANE('',#775);
#777=DIRECTION('',(-0.0174497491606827,0.0174497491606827,0.999695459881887));
#778=VECTOR('',#777,1.);
#779=CARTESIAN_POINT('',(-147.500761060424,31.5015227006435,0.0872354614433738));
#780=LINE('',#779,#778);
#781=CARTESIAN_POINT('',(-144.010065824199,28.0108274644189,-199.894560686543));
#782=VERTEX_POINT('',#781);
#783=EDGE_CURVE('E452',#782,#442,#780,.T.);
#784=ORIENTED_EDGE('',*,*,#783,.F.);
#785=CARTESIAN_POINT('',(-42.3455521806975,28.0418025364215,-198.12));
#786=DIRECTION('',(0.,0.999847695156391,-0.0174524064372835));
#787=DIRECTION('',(0.,-0.0174524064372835,-0.999847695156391));
#788=AXIS2_PLACEMENT_3D('',#785,#786,#787);
#789=ELLIPSE('',#788,101.695488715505,101.68);
#790=CARTESIAN_POINT('',(-42.3455521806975,26.2669715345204,-299.8));
#791=VERTEX_POINT('',#790);
#792=EDGE_CURVE('E481',#791,#782,#789,.T.);
#793=ORIENTED_EDGE('',*,*,#792,.F.);
#794=DIRECTION('',(-1.,0.,0.));
#795=VECTOR('',#794,1.);
#796=CARTESIAN_POINT('',(-152.5,26.2669715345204,-299.8));
#797=LINE('',#796,#795);
#798=CARTESIAN_POINT('',(42.3455521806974,26.2669715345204,-299.8));
#799=VERTEX_POINT('',#798);
#800=EDGE_CURVE('E460',#799,#791,#797,.T.);
#801=ORIENTED_EDGE('',*,*,#800,.F.);
#802=CARTESIAN_POINT('',(42.3455521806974,28.0418025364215,-198.12));
#803=DIRECTION('',(0.,0.999847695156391,-0.0174524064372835));
#804=DIRECTION('',(0.,0.0174524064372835,0.999847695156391));
#805=AXIS2_PLACEMENT_3D('',#802,#803,#804);
#806=ELLIPSE('',#805,101.695488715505,101.68);
#807=CARTESIAN_POINT('',(144.010065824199,28.0108274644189,-199.894560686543));
#808=VERTEX_POINT('',#807);
#809=EDGE_CURVE('E486',#808,#799,#806,.T.);
#810=ORIENTED_EDGE('',*,*,#809,.F.);
#811=DIRECTION('',(0.0174497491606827,0.0174497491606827,0.999695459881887));
#812=VECTOR('',#811,1.);
#813=CARTESIAN_POINT('',(147.48157795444,31.48233959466,-1.0117639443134));
#814=LINE('',#813,#812);
#815=EDGE_CURVE('E477',#808,#618,#814,.T.);
#816=ORIENTED_EDGE('',*,*,#815,.T.);
#817=ORIENTED_EDGE('',*,*,#619,.F.);
#818=DIRECTION('',(0.0174497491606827,0.0174497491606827,0.999695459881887));
#819=VECTOR('',#818,1.);
#820=CARTESIAN_POINT('',(152.480816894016,31.4808168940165,-1.09899940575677));
#821=LINE('',#820,#819);
#822=CARTESIAN_POINT('',(149.009304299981,28.0093042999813,-199.981822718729));
#823=VERTEX_POINT('',#822);
#824=EDGE_CURVE('E780',#823,#614,#821,.T.);
#825=ORIENTED_EDGE('',*,*,#824,.F.);
#826=CARTESIAN_POINT('',(42.3455521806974,28.0418025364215,-198.12));
#827=DIRECTION('',(0.,0.999847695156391,-0.0174524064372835));
#828=DIRECTION('',(0.,0.0174524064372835,0.999847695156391));
#829=AXIS2_PLACEMENT_3D('',#826,#827,#828);
#830=ELLIPSE('',#829,106.696250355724,106.68);
#831=EDGE_CURVE('E758',#823,#47,#830,.T.);
#832=ORIENTED_EDGE('',*,*,#831,.T.);
#833=ORIENTED_EDGE('',*,*,#48,.T.);
#834=CARTESIAN_POINT('',(-42.3455521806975,28.0418025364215,-198.12));
#835=DIRECTION('',(0.,0.999847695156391,-0.0174524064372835));
#836=DIRECTION('',(0.,-0.0174524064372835,-0.999847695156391));
#837=AXIS2_PLACEMENT_3D('',#834,#835,#836);
#838=ELLIPSE('',#837,106.696250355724,106.68);
#839=EDGE_CURVE('E756',#39,#751,#838,.T.);
#840=ORIENTED_EDGE('',*,*,#839,.T.);
#841=ORIENTED_EDGE('',*,*,#752,.T.);
#842=ORIENTED_EDGE('',*,*,#451,.F.);
#843=EDGE_LOOP('',(#784,#793,#801,#810,#816,#817,#825,#832,#833,#840,#841,#842));
#844=FACE_BOUND('',#843,.T.);
#845=ADVANCED_FACE('F948',(#844),#776,.T.);
#846=CARTESIAN_POINT('',(152.5,-31.5,0.));
#847=DIRECTION('',(0.999847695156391,0.,-0.0174524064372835));
#848=DIRECTION('',(-0.0174524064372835,0.,-0.999847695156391));
#849=AXIS2_PLACEMENT_3D('',#846,#847,#848);
#850=PLANE('',#849);
#851=DIRECTION('',(0.0174497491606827,-0.0174497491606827,0.999695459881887));
#852=VECTOR('',#851,1.);
#853=CARTESIAN_POINT('',(152.40712940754,-31.4071294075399,-5.32055267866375));
#854=LINE('',#853,#852);
#855=CARTESIAN_POINT('',(149.009304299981,-28.0093042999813,-199.981822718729));
#856=VERTEX_POINT('',#855);
#857=EDGE_CURVE('E782',#856,#537,#854,.T.);
#858=ORIENTED_EDGE('',*,*,#857,.F.);
#859=DIRECTION('',(0.,1.,0.));
#860=VECTOR('',#859,1.);
#861=CARTESIAN_POINT('',(149.009304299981,-31.5,-199.981822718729));
#862=LINE('',#861,#860);
#863=EDGE_CURVE('E753',#856,#823,#862,.T.);
#864=ORIENTED_EDGE('',*,*,#863,.T.);
#865=ORIENTED_EDGE('',*,*,#824,.T.);
#866=ORIENTED_EDGE('',*,*,#615,.T.);
#867=EDGE_LOOP('',(#858,#864,#865,#866));
#868=FACE_BOUND('',#867,.T.);
#869=ADVANCED_FACE('F961',(#868),#850,.T.);
#870=CARTESIAN_POINT('',(-152.5,-31.5,0.));
#871=DIRECTION('',(0.,-0.999847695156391,-0.0174524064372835));
#872=DIRECTION('',(0.,0.0174524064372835,-0.999847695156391));
#873=AXIS2_PLACEMENT_3D('',#870,#871,#872);
#874=PLANE('',#873);
#875=CARTESIAN_POINT('',(-76.2,-30.4670752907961,-59.1762169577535));
#876=DIRECTION('',(0.,-0.999847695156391,-0.0174524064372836));
#877=DIRECTION('',(0.,0.0174524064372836,-0.999847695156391));
#878=AXIS2_PLACEMENT_3D('',#875,#876,#877);
#879=CIRCLE('',#878,14.6779822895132);
#880=CARTESIAN_POINT('',(-61.5220177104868,-30.4670752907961,-59.1762169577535));
#881=VERTEX_POINT('',#880);
#882=CARTESIAN_POINT('',(-90.8779822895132,-30.4670752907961,-59.1762169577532));
#883=VERTEX_POINT('',#882);
#884=EDGE_CURVE('E693',#881,#883,#879,.T.);
#885=ORIENTED_EDGE('',*,*,#884,.F.);
#886=DIRECTION('',(0.,-0.0174524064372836,0.999847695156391));
#887=VECTOR('',#886,1.);
#888=CARTESIAN_POINT('',(-61.5220177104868,-30.4670752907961,-59.1762169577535));
#889=LINE('',#888,#887);
#890=CARTESIAN_POINT('',(-61.5220177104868,-27.532357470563,-227.306088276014));
#891=VERTEX_POINT('',#890);
#892=EDGE_CURVE('E885',#891,#881,#889,.T.);
#893=ORIENTED_EDGE('',*,*,#892,.F.);
#894=CARTESIAN_POINT('',(-76.2,-27.532357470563,-227.306088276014));
#895=DIRECTION('',(0.,-0.999847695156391,-0.0174524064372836));
#896=DIRECTION('',(0.,0.0174524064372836,-0.999847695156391));
#897=AXIS2_PLACEMENT_3D('',#894,#895,#896);
#898=CIRCLE('',#897,14.6779822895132);
#899=CARTESIAN_POINT('',(-90.8779822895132,-27.532357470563,-227.306088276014));
#900=VERTEX_POINT('',#899);
#901=EDGE_CURVE('E892',#900,#891,#898,.T.);
#902=ORIENTED_EDGE('',*,*,#901,.F.);
#903=DIRECTION('',(0.,0.0174524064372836,-0.999847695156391));
#904=VECTOR('',#903,1.);
#905=CARTESIAN_POINT('',(-90.8779822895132,-30.4670752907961,-59.1762169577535));
#906=LINE('',#905,#904);
#907=EDGE_CURVE('E895',#883,#900,#906,.T.);
#908=ORIENTED_EDGE('',*,*,#907,.F.);
#909=EDGE_LOOP('',(#885,#893,#902,#908));
#910=FACE_BOUND('',#909,.T.);
#911=CARTESIAN_POINT('',(76.2,-30.4670752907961,-59.1762169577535));
#912=DIRECTION('',(0.,-0.999847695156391,-0.0174524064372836));
#913=DIRECTION('',(0.,0.0174524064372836,-0.999847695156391));
#914=AXIS2_PLACEMENT_3D('',#911,#912,#913);
#915=CIRCLE('',#914,14.6779822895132);
#916=CARTESIAN_POINT('',(90.8779822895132,-30.4670752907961,-59.1762169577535));
#917=VERTEX_POINT('',#916);
#918=CARTESIAN_POINT('',(61.5220177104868,-30.4670752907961,-59.1762169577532));
#919=VERTEX_POINT('',#918);
#920=EDGE_CURVE('E878',#917,#919,#915,.T.);
#921=ORIENTED_EDGE('',*,*,#920,.F.);
#922=DIRECTION('',(0.,-0.0174524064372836,0.999847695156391));
#923=VECTOR('',#922,1.);
#924=CARTESIAN_POINT('',(90.8779822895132,-30.4670752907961,-59.1762169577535));
#925=LINE('',#924,#923);
#926=CARTESIAN_POINT('',(90.8779822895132,-27.532357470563,-227.306088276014));
#927=VERTEX_POINT('',#926);
#928=EDGE_CURVE('E865',#927,#917,#925,.T.);
#929=ORIENTED_EDGE('',*,*,#928,.F.);
#930=CARTESIAN_POINT('',(76.2,-27.532357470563,-227.306088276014));
#931=DIRECTION('',(0.,-0.999847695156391,-0.0174524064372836));
#932=DIRECTION('',(0.,0.0174524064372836,-0.999847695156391));
#933=AXIS2_PLACEMENT_3D('',#930,#931,#932);
#934=CIRCLE('',#933,14.6779822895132);
#935=CARTESIAN_POINT('',(61.5220177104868,-27.532357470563,-227.306088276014));
#936=VERTEX_POINT('',#935);
#937=EDGE_CURVE('E872',#936,#927,#934,.T.);
#938=ORIENTED_EDGE('',*,*,#937,.F.);
#939=DIRECTION('',(0.,0.0174524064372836,-0.999847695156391));
#940=VECTOR('',#939,1.);
#941=CARTESIAN_POINT('',(61.5220177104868,-30.4670752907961,-59.1762169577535));
#942=LINE('',#941,#940);
#943=EDGE_CURVE('E875',#919,#936,#942,.T.);
#944=ORIENTED_EDGE('',*,*,#943,.F.);
#945=EDGE_LOOP('',(#921,#929,#938,#944));
#946=FACE_BOUND('',#945,.T.);
#947=CARTESIAN_POINT('',(0.,-30.4670752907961,-59.1762169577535));
#948=DIRECTION('',(0.,-0.999847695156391,-0.0174524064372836));
#949=DIRECTION('',(0.,0.0174524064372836,-0.999847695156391));
#950=AXIS2_PLACEMENT_3D('',#947,#948,#949);
#951=CIRCLE('',#950,14.6779822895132);
#952=CARTESIAN_POINT('',(14.6779822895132,-30.4670752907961,-59.1762169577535));
#953=VERTEX_POINT('',#952);
#954=CARTESIAN_POINT('',(-14.6779822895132,-30.4670752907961,-59.1762169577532));
#955=VERTEX_POINT('',#954);
#956=EDGE_CURVE('E857',#953,#955,#951,.T.);
#957=ORIENTED_EDGE('',*,*,#956,.F.);
#958=DIRECTION('',(0.,-0.0174524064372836,0.999847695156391));
#959=VECTOR('',#958,1.);
#960=CARTESIAN_POINT('',(14.6779822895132,-30.4670752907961,-59.1762169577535));
#961=LINE('',#960,#959);
#962=CARTESIAN_POINT('',(14.6779822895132,-27.532357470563,-227.306088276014));
#963=VERTEX_POINT('',#962);
#964=EDGE_CURVE('E842',#963,#953,#961,.T.);
#965=ORIENTED_EDGE('',*,*,#964,.F.);
#966=CARTESIAN_POINT('',(0.,-27.532357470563,-227.306088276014));
#967=DIRECTION('',(0.,-0.999847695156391,-0.0174524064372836));
#968=DIRECTION('',(0.,0.0174524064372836,-0.999847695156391));
#969=AXIS2_PLACEMENT_3D('',#966,#967,#968);
#970=CIRCLE('',#969,14.6779822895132);
#971=CARTESIAN_POINT('',(-14.6779822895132,-27.532357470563,-227.306088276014));
#972=VERTEX_POINT('',#971);
#973=EDGE_CURVE('E850',#972,#963,#970,.T.);
#974=ORIENTED_EDGE('',*,*,#973,.F.);
#975=DIRECTION('',(0.,0.0174524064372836,-0.999847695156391));
#976=VECTOR('',#975,1.);
#977=CARTESIAN_POINT('',(-14.6779822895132,-30.4670752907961,-59.1762169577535));
#978=LINE('',#977,#976);
#979=EDGE_CURVE('E854',#955,#972,#978,.T.);
#980=ORIENTED_EDGE('',*,*,#979,.F.);
#981=EDGE_LOOP('',(#957,#965,#974,#980));
#982=FACE_BOUND('',#981,.T.);
#983=ORIENTED_EDGE('',*,*,#766,.F.);
#984=CARTESIAN_POINT('',(-42.3455521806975,-28.0418025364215,-198.12));
#985=DIRECTION('',(0.,-0.999847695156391,-0.0174524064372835));
#986=DIRECTION('',(0.,-0.0174524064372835,0.999847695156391));
#987=AXIS2_PLACEMENT_3D('',#984,#985,#986);
#988=ELLIPSE('',#987,106.696250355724,106.68);
#989=EDGE_CURVE('E764',#759,#29,#988,.T.);
#990=ORIENTED_EDGE('',*,*,#989,.T.);
#991=ORIENTED_EDGE('',*,*,#32,.T.);
#992=CARTESIAN_POINT('',(42.3455521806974,-28.0418025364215,-198.12));
#993=DIRECTION('',(0.,-0.999847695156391,-0.0174524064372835));
#994=DIRECTION('',(0.,0.0174524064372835,-0.999847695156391));
#995=AXIS2_PLACEMENT_3D('',#992,#993,#994);
#996=ELLIPSE('',#995,106.696250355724,106.68);
#997=EDGE_CURVE('E766',#31,#856,#996,.T.);
#998=ORIENTED_EDGE('',*,*,#997,.T.);
#999=ORIENTED_EDGE('',*,*,#857,.T.);
#1000=ORIENTED_EDGE('',*,*,#538,.F.);
#1001=EDGE_LOOP('',(#983,#990,#991,#998,#999,#1000));
#1002=FACE_BOUND('',#1001,.T.);
#1003=ADVANCED_FACE('F956',(#910,#946,#982,#1002),#874,.T.);
#1004=CARTESIAN_POINT('',(-42.3455521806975,-31.5,-198.12));
#1005=DIRECTION('',(0.,-1.,0.));
#1006=DIRECTION('',(0.,0.,-1.));
#1007=AXIS2_PLACEMENT_3D('',#1004,#1005,#1006);
#1008=CYLINDRICAL_SURFACE('',#1007,106.68);
#1009=ORIENTED_EDGE('',*,*,#839,.F.);
#1010=ORIENTED_EDGE('',*,*,#40,.F.);
#1011=ORIENTED_EDGE('',*,*,#989,.F.);
#1012=ORIENTED_EDGE('',*,*,#760,.F.);
#1013=EDGE_LOOP('',(#1009,#1010,#1011,#1012));
#1014=FACE_BOUND('',#1013,.T.);
#1015=ADVANCED_FACE('F969',(#1014),#1008,.T.);
#1016=CARTESIAN_POINT('',(42.3455521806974,-31.5,-198.12));
#1017=DIRECTION('',(0.,1.,0.));
#1018=DIRECTION('',(0.,0.,1.));
#1019=AXIS2_PLACEMENT_3D('',#1016,#1017,#1018);
#1020=CYLINDRICAL_SURFACE('',#1019,106.68);
#1021=ORIENTED_EDGE('',*,*,#997,.F.);
#1022=ORIENTED_EDGE('',*,*,#54,.F.);
#1023=ORIENTED_EDGE('',*,*,#831,.F.);
#1024=ORIENTED_EDGE('',*,*,#863,.F.);
#1025=EDGE_LOOP('',(#1021,#1022,#1023,#1024));
#1026=FACE_BOUND('',#1025,.T.);
#1027=ADVANCED_FACE('F967',(#1026),#1020,.T.);
#1028=CARTESIAN_POINT('',(0.,-26.6576555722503,-59.1097232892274));
#1029=DIRECTION('',(0.,-0.999847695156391,-0.0174524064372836));
#1030=DIRECTION('',(0.,0.0174524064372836,-0.999847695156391));
#1031=AXIS2_PLACEMENT_3D('',#1028,#1029,#1030);
#1032=CYLINDRICAL_SURFACE('',#1031,14.6779822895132);
#1033=DIRECTION('',(0.,-0.999847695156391,-0.0174524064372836));
#1034=VECTOR('',#1033,1.);
#1035=CARTESIAN_POINT('',(-14.6779822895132,-26.6576555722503,-59.1097232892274));
#1036=LINE('',#1035,#1034);
#1037=CARTESIAN_POINT('',(-14.6779822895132,-29.1972687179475,-59.1540524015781));
#1038=VERTEX_POINT('',#1037);
#1039=EDGE_CURVE('E818',#1038,#955,#1036,.T.);
#1040=ORIENTED_EDGE('',*,*,#1039,.F.);
#1041=CARTESIAN_POINT('',(0.,-29.1972687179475,-59.1540524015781));
#1042=DIRECTION('',(0.,-0.999847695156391,-0.0174524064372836));
#1043=DIRECTION('',(0.,0.0174524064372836,-0.999847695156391));
#1044=AXIS2_PLACEMENT_3D('',#1041,#1042,#1043);
#1045=CIRCLE('',#1044,14.6779822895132);
#1046=CARTESIAN_POINT('',(14.6779822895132,-29.1972687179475,-59.1540524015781));
#1047=VERTEX_POINT('',#1046);
#1048=EDGE_CURVE('E717',#1038,#1047,#1045,.F.);
#1049=ORIENTED_EDGE('',*,*,#1048,.T.);
#1050=DIRECTION('',(0.,-0.999847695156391,-0.0174524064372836));
#1051=VECTOR('',#1050,1.);
#1052=CARTESIAN_POINT('',(14.6779822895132,-26.6576555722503,-59.1097232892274));
#1053=LINE('',#1052,#1051);
#1054=EDGE_CURVE('E830',#1047,#953,#1053,.T.);
#1055=ORIENTED_EDGE('',*,*,#1054,.T.);
#1056=ORIENTED_EDGE('',*,*,#956,.T.);
#1057=EDGE_LOOP('',(#1040,#1049,#1055,#1056));
#1058=FACE_BOUND('',#1057,.T.);
#1059=ADVANCED_FACE('F811',(#1058),#1032,.F.);
#1060=CARTESIAN_POINT('',(14.6779822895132,-26.6576555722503,-59.1097232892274));
#1061=DIRECTION('',(1.,0.,0.));
#1062=DIRECTION('',(0.,0.,-1.));
#1063=AXIS2_PLACEMENT_3D('',#1060,#1061,#1062);
#1064=PLANE('',#1063);
#1065=ORIENTED_EDGE('',*,*,#1054,.F.);
#1066=DIRECTION('',(0.,-0.0174524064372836,0.999847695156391));
#1067=VECTOR('',#1066,1.);
#1068=CARTESIAN_POINT('',(14.6779822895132,-29.1972687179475,-59.1540524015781));
#1069=LINE('',#1068,#1067);
#1070=CARTESIAN_POINT('',(14.6779822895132,-26.2625508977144,-227.283923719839));
#1071=VERTEX_POINT('',#1070);
#1072=EDGE_CURVE('E723',#1047,#1071,#1069,.F.);
#1073=ORIENTED_EDGE('',*,*,#1072,.T.);
#1074=DIRECTION('',(0.,-0.999847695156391,-0.0174524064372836));
#1075=VECTOR('',#1074,1.);
#1076=CARTESIAN_POINT('',(14.6779822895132,-23.7229377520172,-227.239594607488));
#1077=LINE('',#1076,#1075);
#1078=EDGE_CURVE('E833',#1071,#963,#1077,.T.);
#1079=ORIENTED_EDGE('',*,*,#1078,.T.);
#1080=ORIENTED_EDGE('',*,*,#964,.T.);
#1081=EDGE_LOOP('',(#1065,#1073,#1079,#1080));
#1082=FACE_BOUND('',#1081,.T.);
#1083=ADVANCED_FACE('F975',(#1082),#1064,.F.);
#1084=CARTESIAN_POINT('',(0.,-23.7229377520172,-227.239594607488));
#1085=DIRECTION('',(0.,-0.999847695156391,-0.0174524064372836));
#1086=DIRECTION('',(0.,0.0174524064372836,-0.999847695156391));
#1087=AXIS2_PLACEMENT_3D('',#1084,#1085,#1086);
#1088=CYLINDRICAL_SURFACE('',#1087,14.6779822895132);
#1089=ORIENTED_EDGE('',*,*,#1078,.F.);
#1090=CARTESIAN_POINT('',(0.,-26.2625508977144,-227.283923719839));
#1091=DIRECTION('',(0.,-0.999847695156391,-0.0174524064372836));
#1092=DIRECTION('',(0.,0.0174524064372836,-0.999847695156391));
#1093=AXIS2_PLACEMENT_3D('',#1090,#1091,#1092);
#1094=CIRCLE('',#1093,14.6779822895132);
#1095=CARTESIAN_POINT('',(-14.6779822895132,-26.2625508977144,-227.283923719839));
#1096=VERTEX_POINT('',#1095);
#1097=EDGE_CURVE('E721',#1071,#1096,#1094,.F.);
#1098=ORIENTED_EDGE('',*,*,#1097,.T.);
#1099=DIRECTION('',(0.,-0.999847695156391,-0.0174524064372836));
#1100=VECTOR('',#1099,1.);
#1101=CARTESIAN_POINT('',(-14.6779822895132,-23.7229377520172,-227.239594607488));
#1102=LINE('',#1101,#1100);
#1103=EDGE_CURVE('E839',#1096,#972,#1102,.T.);
#1104=ORIENTED_EDGE('',*,*,#1103,.T.);
#1105=ORIENTED_EDGE('',*,*,#973,.T.);
#1106=EDGE_LOOP('',(#1089,#1098,#1104,#1105));
#1107=FACE_BOUND('',#1106,.T.);
#1108=ADVANCED_FACE('F1101',(#1107),#1088,.F.);
#1109=CARTESIAN_POINT('',(-14.6779822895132,-26.6576555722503,-59.1097232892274));
#1110=DIRECTION('',(-1.,0.,0.));
#1111=DIRECTION('',(0.,0.,1.));
#1112=AXIS2_PLACEMENT_3D('',#1109,#1110,#1111);
#1113=PLANE('',#1112);
#1114=ORIENTED_EDGE('',*,*,#1103,.F.);
#1115=DIRECTION('',(0.,0.0174524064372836,-0.999847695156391));
#1116=VECTOR('',#1115,1.);
#1117=CARTESIAN_POINT('',(-14.6779822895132,-29.1972687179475,-59.1540524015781));
#1118=LINE('',#1117,#1116);
#1119=EDGE_CURVE('E719',#1096,#1038,#1118,.F.);
#1120=ORIENTED_EDGE('',*,*,#1119,.T.);
#1121=ORIENTED_EDGE('',*,*,#1039,.T.);
#1122=ORIENTED_EDGE('',*,*,#979,.T.);
#1123=EDGE_LOOP('',(#1114,#1120,#1121,#1122));
#1124=FACE_BOUND('',#1123,.T.);
#1125=ADVANCED_FACE('F1097',(#1124),#1113,.F.);
#1126=CARTESIAN_POINT('',(0.,-26.6576555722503,-59.1097232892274));
#1127=DIRECTION('',(0.,-0.999847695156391,-0.0174524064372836));
#1128=DIRECTION('',(0.,0.0174524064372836,-0.999847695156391));
#1129=AXIS2_PLACEMENT_3D('',#1126,#1127,#1128);
#1130=PLANE('',#1129);
#1131=CARTESIAN_POINT('',(0.,-23.7229377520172,-227.239594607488));
#1132=DIRECTION('',(0.,-0.999847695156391,-0.0174524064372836));
#1133=DIRECTION('',(0.,0.0174524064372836,-0.999847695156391));
#1134=AXIS2_PLACEMENT_3D('',#1131,#1132,#1133);
#1135=CIRCLE('',#1134,12.1379822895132);
#1136=CARTESIAN_POINT('',(-12.1379822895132,-23.7229377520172,-227.239594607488));
#1137=VERTEX_POINT('',#1136);
#1138=CARTESIAN_POINT('',(12.1379822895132,-23.7229377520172,-227.239594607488));
#1139=VERTEX_POINT('',#1138);
#1140=EDGE_CURVE('E729',#1137,#1139,#1135,.T.);
#1141=ORIENTED_EDGE('',*,*,#1140,.T.);
#1142=DIRECTION('',(0.,-0.0174524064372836,0.999847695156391));
#1143=VECTOR('',#1142,1.);
#1144=CARTESIAN_POINT('',(12.1379822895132,-26.6576555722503,-59.1097232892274));
#1145=LINE('',#1144,#1143);
#1146=CARTESIAN_POINT('',(12.1379822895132,-26.6576555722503,-59.1097232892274));
#1147=VERTEX_POINT('',#1146);
#1148=EDGE_CURVE('E726',#1139,#1147,#1145,.T.);
#1149=ORIENTED_EDGE('',*,*,#1148,.T.);
#1150=CARTESIAN_POINT('',(0.,-26.6576555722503,-59.1097232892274));
#1151=DIRECTION('',(0.,-0.999847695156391,-0.0174524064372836));
#1152=DIRECTION('',(0.,0.0174524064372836,-0.999847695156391));
#1153=AXIS2_PLACEMENT_3D('',#1150,#1151,#1152);
#1154=CIRCLE('',#1153,12.1379822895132);
#1155=CARTESIAN_POINT('',(-12.1379822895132,-26.6576555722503,-59.1097232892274));
#1156=VERTEX_POINT('',#1155);
#1157=EDGE_CURVE('E733',#1147,#1156,#1154,.T.);
#1158=ORIENTED_EDGE('',*,*,#1157,.T.);
#1159=DIRECTION('',(0.,0.0174524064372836,-0.999847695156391));
#1160=VECTOR('',#1159,1.);
#1161=CARTESIAN_POINT('',(-12.1379822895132,-26.6576555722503,-59.1097232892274));
#1162=LINE('',#1161,#1160);
#1163=EDGE_CURVE('E731',#1156,#1137,#1162,.T.);
#1164=ORIENTED_EDGE('',*,*,#1163,.T.);
#1165=EDGE_LOOP('',(#1141,#1149,#1158,#1164));
#1166=FACE_BOUND('',#1165,.T.);
#1167=ADVANCED_FACE('F1093',(#1166),#1130,.T.);
#1168=CARTESIAN_POINT('',(76.2,-26.6576555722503,-59.1097232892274));
#1169=DIRECTION('',(0.,-0.999847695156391,-0.0174524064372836));
#1170=DIRECTION('',(0.,0.0174524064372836,-0.999847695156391));
#1171=AXIS2_PLACEMENT_3D('',#1168,#1169,#1170);
#1172=CYLINDRICAL_SURFACE('',#1171,14.6779822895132);
#1173=DIRECTION('',(0.,-0.999847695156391,-0.0174524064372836));
#1174=VECTOR('',#1173,1.);
#1175=CARTESIAN_POINT('',(61.5220177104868,-26.6576555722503,-59.1097232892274));
#1176=LINE('',#1175,#1174);
#1177=CARTESIAN_POINT('',(61.5220177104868,-29.1972687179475,-59.1540524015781));
#1178=VERTEX_POINT('',#1177);
#1179=EDGE_CURVE('E862',#1178,#919,#1176,.T.);
#1180=ORIENTED_EDGE('',*,*,#1179,.F.);
#1181=CARTESIAN_POINT('',(76.2,-29.1972687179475,-59.1540524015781));
#1182=DIRECTION('',(0.,-0.999847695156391,-0.0174524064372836));
#1183=DIRECTION('',(0.,0.0174524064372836,-0.999847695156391));
#1184=AXIS2_PLACEMENT_3D('',#1181,#1182,#1183);
#1185=CIRCLE('',#1184,14.6779822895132);
#1186=CARTESIAN_POINT('',(90.8779822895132,-29.1972687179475,-59.1540524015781));
#1187=VERTEX_POINT('',#1186);
#1188=EDGE_CURVE('E735',#1178,#1187,#1185,.F.);
#1189=ORIENTED_EDGE('',*,*,#1188,.T.);
#1190=DIRECTION('',(0.,-0.999847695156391,-0.0174524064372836));
#1191=VECTOR('',#1190,1.);
#1192=CARTESIAN_POINT('',(90.8779822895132,-26.6576555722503,-59.1097232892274));
#1193=LINE('',#1192,#1191);
#1194=EDGE_CURVE('E861',#1187,#917,#1193,.T.);
#1195=ORIENTED_EDGE('',*,*,#1194,.T.);
#1196=ORIENTED_EDGE('',*,*,#920,.T.);
#1197=EDGE_LOOP('',(#1180,#1189,#1195,#1196));
#1198=FACE_BOUND('',#1197,.T.);
#1199=ADVANCED_FACE('F1083',(#1198),#1172,.F.);
#1200=CARTESIAN_POINT('',(90.8779822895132,-26.6576555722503,-59.1097232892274));
#1201=DIRECTION('',(1.,0.,0.));
#1202=DIRECTION('',(0.,0.,-1.));
#1203=AXIS2_PLACEMENT_3D('',#1200,#1201,#1202);
#1204=PLANE('',#1203);
#1205=ORIENTED_EDGE('',*,*,#1194,.F.);
#1206=DIRECTION('',(0.,-0.0174524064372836,0.999847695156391));
#1207=VECTOR('',#1206,1.);
#1208=CARTESIAN_POINT('',(90.8779822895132,-29.1972687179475,-59.1540524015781));
#1209=LINE('',#1208,#1207);
#1210=CARTESIAN_POINT('',(90.8779822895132,-26.2625508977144,-227.283923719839));
#1211=VERTEX_POINT('',#1210);
#1212=EDGE_CURVE('E741',#1187,#1211,#1209,.F.);
#1213=ORIENTED_EDGE('',*,*,#1212,.T.);
#1214=DIRECTION('',(0.,-0.999847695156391,-0.0174524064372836));
#1215=VECTOR('',#1214,1.);
#1216=CARTESIAN_POINT('',(90.8779822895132,-23.7229377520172,-227.239594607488));
#1217=LINE('',#1216,#1215);
#1218=EDGE_CURVE('E867',#1211,#927,#1217,.T.);
#1219=ORIENTED_EDGE('',*,*,#1218,.T.);
#1220=ORIENTED_EDGE('',*,*,#928,.T.);
#1221=EDGE_LOOP('',(#1205,#1213,#1219,#1220));
#1222=FACE_BOUND('',#1221,.T.);
#1223=ADVANCED_FACE('F1079',(#1222),#1204,.F.);
#1224=CARTESIAN_POINT('',(76.2,-23.7229377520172,-227.239594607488));
#1225=DIRECTION('',(0.,-0.999847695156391,-0.0174524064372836));
#1226=DIRECTION('',(0.,0.0174524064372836,-0.999847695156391));
#1227=AXIS2_PLACEMENT_3D('',#1224,#1225,#1226);
#1228=CYLINDRICAL_SURFACE('',#1227,14.6779822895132);
#1229=ORIENTED_EDGE('',*,*,#1218,.F.);
#1230=CARTESIAN_POINT('',(76.2,-26.2625508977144,-227.283923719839));
#1231=DIRECTION('',(0.,-0.999847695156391,-0.0174524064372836));
#1232=DIRECTION('',(0.,0.0174524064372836,-0.999847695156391));
#1233=AXIS2_PLACEMENT_3D('',#1230,#1231,#1232);
#1234=CIRCLE('',#1233,14.6779822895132);
#1235=CARTESIAN_POINT('',(61.5220177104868,-26.2625508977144,-227.283923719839));
#1236=VERTEX_POINT('',#1235);
#1237=EDGE_CURVE('E739',#1211,#1236,#1234,.F.);
#1238=ORIENTED_EDGE('',*,*,#1237,.T.);
#1239=DIRECTION('',(0.,-0.999847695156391,-0.0174524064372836));
#1240=VECTOR('',#1239,1.);
#1241=CARTESIAN_POINT('',(61.5220177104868,-23.7229377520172,-227.239594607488));
#1242=LINE('',#1241,#1240);
#1243=EDGE_CURVE('E864',#1236,#936,#1242,.T.);
#1244=ORIENTED_EDGE('',*,*,#1243,.T.);
#1245=ORIENTED_EDGE('',*,*,#937,.T.);
#1246=EDGE_LOOP('',(#1229,#1238,#1244,#1245));
#1247=FACE_BOUND('',#1246,.T.);
#1248=ADVANCED_FACE('F1082',(#1247),#1228,.F.);
#1249=CARTESIAN_POINT('',(61.5220177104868,-26.6576555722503,-59.1097232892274));
#1250=DIRECTION('',(-1.,0.,0.));
#1251=DIRECTION('',(0.,0.,1.));
#1252=AXIS2_PLACEMENT_3D('',#1249,#1250,#1251);
#1253=PLANE('',#1252);
#1254=ORIENTED_EDGE('',*,*,#1243,.F.);
#1255=DIRECTION('',(0.,0.0174524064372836,-0.999847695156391));
#1256=VECTOR('',#1255,1.);
#1257=CARTESIAN_POINT('',(61.5220177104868,-29.1972687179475,-59.1540524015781));
#1258=LINE('',#1257,#1256);
#1259=EDGE_CURVE('E737',#1236,#1178,#1258,.F.);
#1260=ORIENTED_EDGE('',*,*,#1259,.T.);
#1261=ORIENTED_EDGE('',*,*,#1179,.T.);
#1262=ORIENTED_EDGE('',*,*,#943,.T.);
#1263=EDGE_LOOP('',(#1254,#1260,#1261,#1262));
#1264=FACE_BOUND('',#1263,.T.);
#1265=ADVANCED_FACE('F1077',(#1264),#1253,.F.);
#1266=CARTESIAN_POINT('',(76.2,-26.6576555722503,-59.1097232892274));
#1267=DIRECTION('',(0.,-0.999847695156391,-0.0174524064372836));
#1268=DIRECTION('',(0.,0.0174524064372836,-0.999847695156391));
#1269=AXIS2_PLACEMENT_3D('',#1266,#1267,#1268);
#1270=PLANE('',#1269);
#1271=CARTESIAN_POINT('',(76.2,-23.7229377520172,-227.239594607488));
#1272=DIRECTION('',(0.,-0.999847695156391,-0.0174524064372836));
#1273=DIRECTION('',(0.,0.0174524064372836,-0.999847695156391));
#1274=AXIS2_PLACEMENT_3D('',#1271,#1272,#1273);
#1275=CIRCLE('',#1274,12.1379822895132);
#1276=CARTESIAN_POINT('',(64.0620177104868,-23.7229377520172,-227.239594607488));
#1277=VERTEX_POINT('',#1276);
#1278=CARTESIAN_POINT('',(88.3379822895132,-23.7229377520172,-227.239594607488));
#1279=VERTEX_POINT('',#1278);
#1280=EDGE_CURVE('E747',#1277,#1279,#1275,.T.);
#1281=ORIENTED_EDGE('',*,*,#1280,.T.);
#1282=DIRECTION('',(0.,-0.0174524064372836,0.999847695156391));
#1283=VECTOR('',#1282,1.);
#1284=CARTESIAN_POINT('',(88.3379822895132,-26.6576555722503,-59.1097232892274));
#1285=LINE('',#1284,#1283);
#1286=CARTESIAN_POINT('',(88.3379822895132,-26.6576555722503,-59.1097232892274));
#1287=VERTEX_POINT('',#1286);
#1288=EDGE_CURVE('E744',#1279,#1287,#1285,.T.);
#1289=ORIENTED_EDGE('',*,*,#1288,.T.);
#1290=CARTESIAN_POINT('',(76.2,-26.6576555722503,-59.1097232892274));
#1291=DIRECTION('',(0.,-0.999847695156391,-0.0174524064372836));
#1292=DIRECTION('',(0.,0.0174524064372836,-0.999847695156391));
#1293=AXIS2_PLACEMENT_3D('',#1290,#1291,#1292);
#1294=CIRCLE('',#1293,12.1379822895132);
#1295=CARTESIAN_POINT('',(64.0620177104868,-26.6576555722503,-59.1097232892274));
#1296=VERTEX_POINT('',#1295);
#1297=EDGE_CURVE('E751',#1287,#1296,#1294,.T.);
#1298=ORIENTED_EDGE('',*,*,#1297,.T.);
#1299=DIRECTION('',(0.,0.0174524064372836,-0.999847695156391));
#1300=VECTOR('',#1299,1.);
#1301=CARTESIAN_POINT('',(64.0620177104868,-26.6576555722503,-59.1097232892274));
#1302=LINE('',#1301,#1300);
#1303=EDGE_CURVE('E749',#1296,#1277,#1302,.T.);
#1304=ORIENTED_EDGE('',*,*,#1303,.T.);
#1305=EDGE_LOOP('',(#1281,#1289,#1298,#1304));
#1306=FACE_BOUND('',#1305,.T.);
#1307=ADVANCED_FACE('F1074',(#1306),#1270,.T.);
#1308=CARTESIAN_POINT('',(-76.2,-26.6576555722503,-59.1097232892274));
#1309=DIRECTION('',(0.,-0.999847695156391,-0.0174524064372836));
#1310=DIRECTION('',(0.,0.0174524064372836,-0.999847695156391));
#1311=AXIS2_PLACEMENT_3D('',#1308,#1309,#1310);
#1312=CYLINDRICAL_SURFACE('',#1311,14.6779822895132);
#1313=DIRECTION('',(0.,-0.999847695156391,-0.0174524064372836));
#1314=VECTOR('',#1313,1.);
#1315=CARTESIAN_POINT('',(-90.8779822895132,-26.6576555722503,-59.1097232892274));
#1316=LINE('',#1315,#1314);
#1317=CARTESIAN_POINT('',(-90.8779822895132,-29.1972687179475,-59.1540524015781));
#1318=VERTEX_POINT('',#1317);
#1319=EDGE_CURVE('E882',#1318,#883,#1316,.T.);
#1320=ORIENTED_EDGE('',*,*,#1319,.F.);
#1321=CARTESIAN_POINT('',(-76.2,-29.1972687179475,-59.1540524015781));
#1322=DIRECTION('',(0.,-0.999847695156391,-0.0174524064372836));
#1323=DIRECTION('',(0.,0.0174524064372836,-0.999847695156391));
#1324=AXIS2_PLACEMENT_3D('',#1321,#1322,#1323);
#1325=CIRCLE('',#1324,14.6779822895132);
#1326=CARTESIAN_POINT('',(-61.5220177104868,-29.1972687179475,-59.1540524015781));
#1327=VERTEX_POINT('',#1326);
#1328=EDGE_CURVE('E667',#1318,#1327,#1325,.F.);
#1329=ORIENTED_EDGE('',*,*,#1328,.T.);
#1330=DIRECTION('',(0.,-0.999847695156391,-0.0174524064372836));
#1331=VECTOR('',#1330,1.);
#1332=CARTESIAN_POINT('',(-61.5220177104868,-26.6576555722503,-59.1097232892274));
#1333=LINE('',#1332,#1331);
#1334=EDGE_CURVE('E881',#1327,#881,#1333,.T.);
#1335=ORIENTED_EDGE('',*,*,#1334,.T.);
#1336=ORIENTED_EDGE('',*,*,#884,.T.);
#1337=EDGE_LOOP('',(#1320,#1329,#1335,#1336));
#1338=FACE_BOUND('',#1337,.T.);
#1339=ADVANCED_FACE('F1040',(#1338),#1312,.F.);
#1340=CARTESIAN_POINT('',(-61.5220177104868,-26.6576555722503,-59.1097232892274));
#1341=DIRECTION('',(1.,0.,0.));
#1342=DIRECTION('',(0.,0.,-1.));
#1343=AXIS2_PLACEMENT_3D('',#1340,#1341,#1342);
#1344=PLANE('',#1343);
#1345=ORIENTED_EDGE('',*,*,#1334,.F.);
#1346=DIRECTION('',(0.,-0.0174524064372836,0.999847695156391));
#1347=VECTOR('',#1346,1.);
#1348=CARTESIAN_POINT('',(-61.5220177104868,-29.1972687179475,-59.1540524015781));
#1349=LINE('',#1348,#1347);
#1350=CARTESIAN_POINT('',(-61.5220177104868,-26.2625508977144,-227.283923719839));
#1351=VERTEX_POINT('',#1350);
#1352=EDGE_CURVE('E705',#1327,#1351,#1349,.F.);
#1353=ORIENTED_EDGE('',*,*,#1352,.T.);
#1354=DIRECTION('',(0.,-0.999847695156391,-0.0174524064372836));
#1355=VECTOR('',#1354,1.);
#1356=CARTESIAN_POINT('',(-61.5220177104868,-23.7229377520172,-227.239594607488));
#1357=LINE('',#1356,#1355);
#1358=EDGE_CURVE('E887',#1351,#891,#1357,.T.);
#1359=ORIENTED_EDGE('',*,*,#1358,.T.);
#1360=ORIENTED_EDGE('',*,*,#892,.T.);
#1361=EDGE_LOOP('',(#1345,#1353,#1359,#1360));
#1362=FACE_BOUND('',#1361,.T.);
#1363=ADVANCED_FACE('F1052',(#1362),#1344,.F.);
#1364=CARTESIAN_POINT('',(-76.2,-23.7229377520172,-227.239594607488));
#1365=DIRECTION('',(0.,-0.999847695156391,-0.0174524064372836));
#1366=DIRECTION('',(0.,0.0174524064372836,-0.999847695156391));
#1367=AXIS2_PLACEMENT_3D('',#1364,#1365,#1366);
#1368=CYLINDRICAL_SURFACE('',#1367,14.6779822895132);
#1369=ORIENTED_EDGE('',*,*,#1358,.F.);
#1370=CARTESIAN_POINT('',(-76.2,-26.2625508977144,-227.283923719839));
#1371=DIRECTION('',(0.,-0.999847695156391,-0.0174524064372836));
#1372=DIRECTION('',(0.,0.0174524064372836,-0.999847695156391));
#1373=AXIS2_PLACEMENT_3D('',#1370,#1371,#1372);
#1374=CIRCLE('',#1373,14.6779822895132);
#1375=CARTESIAN_POINT('',(-90.8779822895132,-26.2625508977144,-227.283923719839));
#1376=VERTEX_POINT('',#1375);
#1377=EDGE_CURVE('E703',#1351,#1376,#1374,.F.);
#1378=ORIENTED_EDGE('',*,*,#1377,.T.);
#1379=DIRECTION('',(0.,-0.999847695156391,-0.0174524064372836));
#1380=VECTOR('',#1379,1.);
#1381=CARTESIAN_POINT('',(-90.8779822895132,-23.7229377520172,-227.239594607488));
#1382=LINE('',#1381,#1380);
#1383=EDGE_CURVE('E884',#1376,#900,#1382,.T.);
#1384=ORIENTED_EDGE('',*,*,#1383,.T.);
#1385=ORIENTED_EDGE('',*,*,#901,.T.);
#1386=EDGE_LOOP('',(#1369,#1378,#1384,#1385));
#1387=FACE_BOUND('',#1386,.T.);
#1388=ADVANCED_FACE('F1050',(#1387),#1368,.F.);
#1389=CARTESIAN_POINT('',(-90.8779822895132,-26.6576555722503,-59.1097232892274));
#1390=DIRECTION('',(-1.,0.,0.));
#1391=DIRECTION('',(0.,0.,1.));
#1392=AXIS2_PLACEMENT_3D('',#1389,#1390,#1391);
#1393=PLANE('',#1392);
#1394=ORIENTED_EDGE('',*,*,#1383,.F.);
#1395=DIRECTION('',(0.,0.0174524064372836,-0.999847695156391));
#1396=VECTOR('',#1395,1.);
#1397=CARTESIAN_POINT('',(-90.8779822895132,-29.1972687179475,-59.1540524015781));
#1398=LINE('',#1397,#1396);
#1399=EDGE_CURVE('E701',#1376,#1318,#1398,.F.);
#1400=ORIENTED_EDGE('',*,*,#1399,.T.);
#1401=ORIENTED_EDGE('',*,*,#1319,.T.);
#1402=ORIENTED_EDGE('',*,*,#907,.T.);
#1403=EDGE_LOOP('',(#1394,#1400,#1401,#1402));
#1404=FACE_BOUND('',#1403,.T.);
#1405=ADVANCED_FACE('F1038',(#1404),#1393,.F.);
#1406=CARTESIAN_POINT('',(-76.2,-26.6576555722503,-59.1097232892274));
#1407=DIRECTION('',(0.,-0.999847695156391,-0.0174524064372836));
#1408=DIRECTION('',(0.,0.0174524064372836,-0.999847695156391));
#1409=AXIS2_PLACEMENT_3D('',#1406,#1407,#1408);
#1410=PLANE('',#1409);
#1411=CARTESIAN_POINT('',(-76.2,-23.7229377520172,-227.239594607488));
#1412=DIRECTION('',(0.,-0.999847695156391,-0.0174524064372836));
#1413=DIRECTION('',(0.,0.0174524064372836,-0.999847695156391));
#1414=AXIS2_PLACEMENT_3D('',#1411,#1412,#1413);
#1415=CIRCLE('',#1414,12.1379822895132);
#1416=CARTESIAN_POINT('',(-88.3379822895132,-23.7229377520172,-227.239594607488));
#1417=VERTEX_POINT('',#1416);
#1418=CARTESIAN_POINT('',(-64.0620177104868,-23.7229377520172,-227.239594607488));
#1419=VERTEX_POINT('',#1418);
#1420=EDGE_CURVE('E711',#1417,#1419,#1415,.T.);
#1421=ORIENTED_EDGE('',*,*,#1420,.T.);
#1422=DIRECTION('',(0.,-0.0174524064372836,0.999847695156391));
#1423=VECTOR('',#1422,1.);
#1424=CARTESIAN_POINT('',(-64.0620177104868,-26.6576555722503,-59.1097232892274));
#1425=LINE('',#1424,#1423);
#1426=CARTESIAN_POINT('',(-64.0620177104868,-26.6576555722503,-59.1097232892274));
#1427=VERTEX_POINT('',#1426);
#1428=EDGE_CURVE('E708',#1419,#1427,#1425,.T.);
#1429=ORIENTED_EDGE('',*,*,#1428,.T.);
#1430=CARTESIAN_POINT('',(-76.2,-26.6576555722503,-59.1097232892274));
#1431=DIRECTION('',(0.,-0.999847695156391,-0.0174524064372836));
#1432=DIRECTION('',(0.,0.0174524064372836,-0.999847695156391));
#1433=AXIS2_PLACEMENT_3D('',#1430,#1431,#1432);
#1434=CIRCLE('',#1433,12.1379822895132);
#1435=CARTESIAN_POINT('',(-88.3379822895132,-26.6576555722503,-59.1097232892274));
#1436=VERTEX_POINT('',#1435);
#1437=EDGE_CURVE('E715',#1427,#1436,#1434,.T.);
#1438=ORIENTED_EDGE('',*,*,#1437,.T.);
#1439=DIRECTION('',(0.,0.0174524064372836,-0.999847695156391));
#1440=VECTOR('',#1439,1.);
#1441=CARTESIAN_POINT('',(-88.3379822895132,-26.6576555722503,-59.1097232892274));
#1442=LINE('',#1441,#1440);
#1443=EDGE_CURVE('E713',#1436,#1417,#1442,.T.);
#1444=ORIENTED_EDGE('',*,*,#1443,.T.);
#1445=EDGE_LOOP('',(#1421,#1429,#1438,#1444));
#1446=FACE_BOUND('',#1445,.T.);
#1447=ADVANCED_FACE('F996',(#1446),#1410,.T.);
#1448=CARTESIAN_POINT('',(64.0620177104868,-29.1972687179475,-59.1540524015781));
#1449=DIRECTION('',(0.,0.0174524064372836,-0.999847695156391));
#1450=DIRECTION('',(0.,0.999847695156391,0.0174524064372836));
#1451=AXIS2_PLACEMENT_3D('',#1448,#1449,#1450);
#1452=CYLINDRICAL_SURFACE('',#1451,2.54);
#1453=CARTESIAN_POINT('',(64.0620177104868,-29.1972687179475,-59.1540524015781));
#1454=DIRECTION('',(0.,0.0174524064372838,-0.999847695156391));
#1455=DIRECTION('',(0.,0.999847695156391,0.0174524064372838));
#1456=AXIS2_PLACEMENT_3D('',#1453,#1454,#1455);
#1457=CIRCLE('',#1456,2.54);
#1458=EDGE_CURVE('E694',#1178,#1296,#1457,.T.);
#1459=ORIENTED_EDGE('',*,*,#1458,.F.);
#1460=ORIENTED_EDGE('',*,*,#1259,.F.);
#1461=CARTESIAN_POINT('',(64.0620177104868,-26.2625508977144,-227.283923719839));
#1462=DIRECTION('',(0.,-0.0174524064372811,0.999847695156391));
#1463=DIRECTION('',(0.,-0.999847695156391,-0.0174524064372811));
#1464=AXIS2_PLACEMENT_3D('',#1461,#1462,#1463);
#1465=CIRCLE('',#1464,2.54);
#1466=EDGE_CURVE('E690',#1277,#1236,#1465,.T.);
#1467=ORIENTED_EDGE('',*,*,#1466,.F.);
#1468=ORIENTED_EDGE('',*,*,#1303,.F.);
#1469=EDGE_LOOP('',(#1459,#1460,#1467,#1468));
#1470=FACE_BOUND('',#1469,.T.);
#1471=ADVANCED_FACE('F992',(#1470),#1452,.F.);
#1472=CARTESIAN_POINT('',(76.2,-26.2625508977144,-227.283923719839));
#1473=DIRECTION('',(0.,-0.999847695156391,-0.0174524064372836));
#1474=DIRECTION('',(0.,0.0174524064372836,-0.999847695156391));
#1475=AXIS2_PLACEMENT_3D('',#1472,#1473,#1474);
#1476=TOROIDAL_SURFACE('',#1475,12.1379822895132,2.54);
#1477=ORIENTED_EDGE('',*,*,#1466,.T.);
#1478=ORIENTED_EDGE('',*,*,#1237,.F.);
#1479=CARTESIAN_POINT('',(88.3379822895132,-26.2625508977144,-227.283923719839));
#1480=DIRECTION('',(0.,0.0174524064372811,-0.999847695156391));
#1481=DIRECTION('',(0.,0.999847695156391,0.0174524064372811));
#1482=AXIS2_PLACEMENT_3D('',#1479,#1480,#1481);
#1483=CIRCLE('',#1482,2.54);
#1484=EDGE_CURVE('E697',#1279,#1211,#1483,.T.);
#1485=ORIENTED_EDGE('',*,*,#1484,.F.);
#1486=ORIENTED_EDGE('',*,*,#1280,.F.);
#1487=EDGE_LOOP('',(#1477,#1478,#1485,#1486));
#1488=FACE_BOUND('',#1487,.T.);
#1489=ADVANCED_FACE('F988',(#1488),#1476,.F.);
#1490=CARTESIAN_POINT('',(76.2,-29.1972687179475,-59.1540524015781));
#1491=DIRECTION('',(0.,-0.999847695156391,-0.0174524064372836));
#1492=DIRECTION('',(0.,0.0174524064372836,-0.999847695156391));
#1493=AXIS2_PLACEMENT_3D('',#1490,#1491,#1492);
#1494=TOROIDAL_SURFACE('',#1493,12.1379822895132,2.54);
#1495=ORIENTED_EDGE('',*,*,#1458,.T.);
#1496=ORIENTED_EDGE('',*,*,#1297,.F.);
#1497=CARTESIAN_POINT('',(88.3379822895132,-29.1972687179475,-59.1540524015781));
#1498=DIRECTION('',(0.,-0.0174524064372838,0.999847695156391));
#1499=DIRECTION('',(0.,-0.999847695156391,-0.0174524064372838));
#1500=AXIS2_PLACEMENT_3D('',#1497,#1498,#1499);
#1501=CIRCLE('',#1500,2.54);
#1502=EDGE_CURVE('E683',#1187,#1287,#1501,.T.);
#1503=ORIENTED_EDGE('',*,*,#1502,.F.);
#1504=ORIENTED_EDGE('',*,*,#1188,.F.);
#1505=EDGE_LOOP('',(#1495,#1496,#1503,#1504));
#1506=FACE_BOUND('',#1505,.T.);
#1507=ADVANCED_FACE('F984',(#1506),#1494,.F.);
#1508=CARTESIAN_POINT('',(88.3379822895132,-29.1972687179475,-59.1540524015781));
#1509=DIRECTION('',(0.,-0.0174524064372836,0.999847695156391));
#1510=DIRECTION('',(0.,-0.999847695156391,-0.0174524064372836));
#1511=AXIS2_PLACEMENT_3D('',#1508,#1509,#1510);
#1512=CYLINDRICAL_SURFACE('',#1511,2.54);
#1513=ORIENTED_EDGE('',*,*,#1484,.T.);
#1514=ORIENTED_EDGE('',*,*,#1212,.F.);
#1515=ORIENTED_EDGE('',*,*,#1502,.T.);
#1516=ORIENTED_EDGE('',*,*,#1288,.F.);
#1517=EDGE_LOOP('',(#1513,#1514,#1515,#1516));
#1518=FACE_BOUND('',#1517,.T.);
#1519=ADVANCED_FACE('F980',(#1518),#1512,.F.);
#1520=CARTESIAN_POINT('',(-12.1379822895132,-29.1972687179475,-59.1540524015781));
#1521=DIRECTION('',(0.,0.0174524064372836,-0.999847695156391));
#1522=DIRECTION('',(0.,0.999847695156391,0.0174524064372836));
#1523=AXIS2_PLACEMENT_3D('',#1520,#1521,#1522);
#1524=CYLINDRICAL_SURFACE('',#1523,2.54);
#1525=CARTESIAN_POINT('',(-12.1379822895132,-29.1972687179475,-59.1540524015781));
#1526=DIRECTION('',(0.,0.0174524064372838,-0.999847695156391));
#1527=DIRECTION('',(0.,0.999847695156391,0.0174524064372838));
#1528=AXIS2_PLACEMENT_3D('',#1525,#1526,#1527);
#1529=CIRCLE('',#1528,2.54);
#1530=EDGE_CURVE('E684',#1038,#1156,#1529,.T.);
#1531=ORIENTED_EDGE('',*,*,#1530,.F.);
#1532=ORIENTED_EDGE('',*,*,#1119,.F.);
#1533=CARTESIAN_POINT('',(-12.1379822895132,-26.2625508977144,-227.283923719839));
#1534=DIRECTION('',(0.,-0.0174524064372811,0.999847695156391));
#1535=DIRECTION('',(0.,-0.999847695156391,-0.0174524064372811));
#1536=AXIS2_PLACEMENT_3D('',#1533,#1534,#1535);
#1537=CIRCLE('',#1536,2.54);
#1538=EDGE_CURVE('E680',#1137,#1096,#1537,.T.);
#1539=ORIENTED_EDGE('',*,*,#1538,.F.);
#1540=ORIENTED_EDGE('',*,*,#1163,.F.);
#1541=EDGE_LOOP('',(#1531,#1532,#1539,#1540));
#1542=FACE_BOUND('',#1541,.T.);
#1543=ADVANCED_FACE('F983',(#1542),#1524,.F.);
#1544=CARTESIAN_POINT('',(0.,-26.2625508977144,-227.283923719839));
#1545=DIRECTION('',(0.,-0.999847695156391,-0.0174524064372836));
#1546=DIRECTION('',(0.,0.0174524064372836,-0.999847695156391));
#1547=AXIS2_PLACEMENT_3D('',#1544,#1545,#1546);
#1548=TOROIDAL_SURFACE('',#1547,12.1379822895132,2.54);
#1549=ORIENTED_EDGE('',*,*,#1538,.T.);
#1550=ORIENTED_EDGE('',*,*,#1097,.F.);
#1551=CARTESIAN_POINT('',(12.1379822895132,-26.2625508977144,-227.283923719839));
#1552=DIRECTION('',(0.,0.0174524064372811,-0.999847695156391));
#1553=DIRECTION('',(0.,0.999847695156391,0.0174524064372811));
#1554=AXIS2_PLACEMENT_3D('',#1551,#1552,#1553);
#1555=CIRCLE('',#1554,2.54);
#1556=EDGE_CURVE('E687',#1139,#1071,#1555,.T.);
#1557=ORIENTED_EDGE('',*,*,#1556,.F.);
#1558=ORIENTED_EDGE('',*,*,#1140,.F.);
#1559=EDGE_LOOP('',(#1549,#1550,#1557,#1558));
#1560=FACE_BOUND('',#1559,.T.);
#1561=ADVANCED_FACE('F1005',(#1560),#1548,.F.);
#1562=CARTESIAN_POINT('',(0.,-29.1972687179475,-59.1540524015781));
#1563=DIRECTION('',(0.,-0.999847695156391,-0.0174524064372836));
#1564=DIRECTION('',(0.,0.0174524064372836,-0.999847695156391));
#1565=AXIS2_PLACEMENT_3D('',#1562,#1563,#1564);
#1566=TOROIDAL_SURFACE('',#1565,12.1379822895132,2.54);
#1567=ORIENTED_EDGE('',*,*,#1530,.T.);
#1568=ORIENTED_EDGE('',*,*,#1157,.F.);
#1569=CARTESIAN_POINT('',(12.1379822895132,-29.1972687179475,-59.1540524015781));
#1570=DIRECTION('',(0.,-0.0174524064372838,0.999847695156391));
#1571=DIRECTION('',(0.,-0.999847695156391,-0.0174524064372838));
#1572=AXIS2_PLACEMENT_3D('',#1569,#1570,#1571);
#1573=CIRCLE('',#1572,2.54);
#1574=EDGE_CURVE('E671',#1047,#1147,#1573,.T.);
#1575=ORIENTED_EDGE('',*,*,#1574,.F.);
#1576=ORIENTED_EDGE('',*,*,#1048,.F.);
#1577=EDGE_LOOP('',(#1567,#1568,#1575,#1576));
#1578=FACE_BOUND('',#1577,.T.);
#1579=ADVANCED_FACE('F1001',(#1578),#1566,.F.);
#1580=CARTESIAN_POINT('',(12.1379822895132,-29.1972687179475,-59.1540524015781));
#1581=DIRECTION('',(0.,-0.0174524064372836,0.999847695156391));
#1582=DIRECTION('',(0.,-0.999847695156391,-0.0174524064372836));
#1583=AXIS2_PLACEMENT_3D('',#1580,#1581,#1582);
#1584=CYLINDRICAL_SURFACE('',#1583,2.54);
#1585=ORIENTED_EDGE('',*,*,#1556,.T.);
#1586=ORIENTED_EDGE('',*,*,#1072,.F.);
#1587=ORIENTED_EDGE('',*,*,#1574,.T.);
#1588=ORIENTED_EDGE('',*,*,#1148,.F.);
#1589=EDGE_LOOP('',(#1585,#1586,#1587,#1588));
#1590=FACE_BOUND('',#1589,.T.);
#1591=ADVANCED_FACE('F998',(#1590),#1584,.F.);
#1592=CARTESIAN_POINT('',(-88.3379822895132,-29.1972687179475,-59.1540524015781));
#1593=DIRECTION('',(0.,0.0174524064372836,-0.999847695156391));
#1594=DIRECTION('',(0.,0.999847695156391,0.0174524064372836));
#1595=AXIS2_PLACEMENT_3D('',#1592,#1593,#1594);
#1596=CYLINDRICAL_SURFACE('',#1595,2.54);
#1597=CARTESIAN_POINT('',(-88.3379822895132,-29.1972687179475,-59.1540524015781));
#1598=DIRECTION('',(0.,0.0174524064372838,-0.999847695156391));
#1599=DIRECTION('',(0.,0.999847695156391,0.0174524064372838));
#1600=AXIS2_PLACEMENT_3D('',#1597,#1598,#1599);
#1601=CIRCLE('',#1600,2.54);
#1602=EDGE_CURVE('E672',#1318,#1436,#1601,.T.);
#1603=ORIENTED_EDGE('',*,*,#1602,.F.);
#1604=ORIENTED_EDGE('',*,*,#1399,.F.);
#1605=CARTESIAN_POINT('',(-88.3379822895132,-26.2625508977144,-227.283923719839));
#1606=DIRECTION('',(0.,-0.0174524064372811,0.999847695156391));
#1607=DIRECTION('',(0.,-0.999847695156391,-0.0174524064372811));
#1608=AXIS2_PLACEMENT_3D('',#1605,#1606,#1607);
#1609=CIRCLE('',#1608,2.54);
#1610=EDGE_CURVE('E668',#1417,#1376,#1609,.T.);
#1611=ORIENTED_EDGE('',*,*,#1610,.F.);
#1612=ORIENTED_EDGE('',*,*,#1443,.F.);
#1613=EDGE_LOOP('',(#1603,#1604,#1611,#1612));
#1614=FACE_BOUND('',#1613,.T.);
#1615=ADVANCED_FACE('F633',(#1614),#1596,.F.);
#1616=CARTESIAN_POINT('',(-76.2,-26.2625508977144,-227.283923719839));
#1617=DIRECTION('',(0.,-0.999847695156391,-0.0174524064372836));
#1618=DIRECTION('',(0.,0.0174524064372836,-0.999847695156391));
#1619=AXIS2_PLACEMENT_3D('',#1616,#1617,#1618);
#1620=TOROIDAL_SURFACE('',#1619,12.1379822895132,2.54);
#1621=ORIENTED_EDGE('',*,*,#1610,.T.);
#1622=ORIENTED_EDGE('',*,*,#1377,.F.);
#1623=CARTESIAN_POINT('',(-64.0620177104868,-26.2625508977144,-227.283923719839));
#1624=DIRECTION('',(0.,0.0174524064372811,-0.999847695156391));
#1625=DIRECTION('',(0.,0.999847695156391,0.0174524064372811));
#1626=AXIS2_PLACEMENT_3D('',#1623,#1624,#1625);
#1627=CIRCLE('',#1626,2.54);
#1628=EDGE_CURVE('E675',#1419,#1351,#1627,.T.);
#1629=ORIENTED_EDGE('',*,*,#1628,.F.);
#1630=ORIENTED_EDGE('',*,*,#1420,.F.);
#1631=EDGE_LOOP('',(#1621,#1622,#1629,#1630));
#1632=FACE_BOUND('',#1631,.T.);
#1633=ADVANCED_FACE('F1019',(#1632),#1620,.F.);
#1634=CARTESIAN_POINT('',(-76.2,-29.1972687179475,-59.1540524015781));
#1635=DIRECTION('',(0.,-0.999847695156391,-0.0174524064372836));
#1636=DIRECTION('',(0.,0.0174524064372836,-0.999847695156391));
#1637=AXIS2_PLACEMENT_3D('',#1634,#1635,#1636);
#1638=TOROIDAL_SURFACE('',#1637,12.1379822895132,2.54);
#1639=ORIENTED_EDGE('',*,*,#1602,.T.);
#1640=ORIENTED_EDGE('',*,*,#1437,.F.);
#1641=CARTESIAN_POINT('',(-64.0620177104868,-29.1972687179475,-59.1540524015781));
#1642=DIRECTION('',(0.,-0.0174524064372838,0.999847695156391));
#1643=DIRECTION('',(0.,-0.999847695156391,-0.0174524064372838));
#1644=AXIS2_PLACEMENT_3D('',#1641,#1642,#1643);
#1645=CIRCLE('',#1644,2.54);
#1646=EDGE_CURVE('E677',#1327,#1427,#1645,.T.);
#1647=ORIENTED_EDGE('',*,*,#1646,.F.);
#1648=ORIENTED_EDGE('',*,*,#1328,.F.);
#1649=EDGE_LOOP('',(#1639,#1640,#1647,#1648));
#1650=FACE_BOUND('',#1649,.T.);
#1651=ADVANCED_FACE('F1016',(#1650),#1638,.F.);
#1652=CARTESIAN_POINT('',(-64.0620177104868,-29.1972687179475,-59.1540524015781));
#1653=DIRECTION('',(0.,-0.0174524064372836,0.999847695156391));
#1654=DIRECTION('',(0.,-0.999847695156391,-0.0174524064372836));
#1655=AXIS2_PLACEMENT_3D('',#1652,#1653,#1654);
#1656=CYLINDRICAL_SURFACE('',#1655,2.54);
#1657=ORIENTED_EDGE('',*,*,#1628,.T.);
#1658=ORIENTED_EDGE('',*,*,#1352,.F.);
#1659=ORIENTED_EDGE('',*,*,#1646,.T.);
#1660=ORIENTED_EDGE('',*,*,#1428,.F.);
#1661=EDGE_LOOP('',(#1657,#1658,#1659,#1660));
#1662=FACE_BOUND('',#1661,.T.);
#1663=ADVANCED_FACE('F1013',(#1662),#1656,.F.);
#1664=CARTESIAN_POINT('',(-147.500761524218,-31.5,0.0872620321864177));
#1665=DIRECTION('',(-0.999847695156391,0.,-0.0174524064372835));
#1666=DIRECTION('',(-0.0174524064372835,0.,0.999847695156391));
#1667=AXIS2_PLACEMENT_3D('',#1664,#1665,#1666);
#1668=PLANE('',#1667);
#1669=ORIENTED_EDGE('',*,*,#783,.T.);
#1670=ORIENTED_EDGE('',*,*,#443,.F.);
#1671=DIRECTION('',(-0.0174497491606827,-0.0174497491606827,0.999695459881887));
#1672=VECTOR('',#1671,1.);
#1673=CARTESIAN_POINT('',(-147.502283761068,-26.5022837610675,0.174470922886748));
#1674=LINE('',#1673,#1672);
#1675=CARTESIAN_POINT('',(-144.010065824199,-23.0100658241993,-199.894560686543));
#1676=VERTEX_POINT('',#1675);
#1677=EDGE_CURVE('E468',#1676,#365,#1674,.T.);
#1678=ORIENTED_EDGE('',*,*,#1677,.F.);
#1679=DIRECTION('',(0.,1.,0.));
#1680=VECTOR('',#1679,1.);
#1681=CARTESIAN_POINT('',(-144.010065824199,-31.5,-199.894560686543));
#1682=LINE('',#1681,#1680);
#1683=EDGE_CURVE('E423',#782,#1676,#1682,.F.);
#1684=ORIENTED_EDGE('',*,*,#1683,.F.);
#1685=EDGE_LOOP('',(#1669,#1670,#1678,#1684));
#1686=FACE_BOUND('',#1685,.T.);
#1687=ADVANCED_FACE('F433',(#1686),#1668,.F.);
#1688=CARTESIAN_POINT('',(147.500761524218,-31.5,0.0872620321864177));
#1689=DIRECTION('',(0.999847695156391,0.,-0.0174524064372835));
#1690=DIRECTION('',(-0.0174524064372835,0.,-0.999847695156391));
#1691=AXIS2_PLACEMENT_3D('',#1688,#1689,#1690);
#1692=PLANE('',#1691);
#1693=DIRECTION('',(0.0174497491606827,-0.0174497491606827,0.999695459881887));
#1694=VECTOR('',#1693,1.);
#1695=CARTESIAN_POINT('',(147.409413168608,-26.4094131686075,-5.146081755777));
#1696=LINE('',#1695,#1694);
#1697=CARTESIAN_POINT('',(144.010065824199,-23.0100658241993,-199.894560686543));
#1698=VERTEX_POINT('',#1697);
#1699=EDGE_CURVE('E475',#1698,#367,#1696,.T.);
#1700=ORIENTED_EDGE('',*,*,#1699,.T.);
#1701=ORIENTED_EDGE('',*,*,#736,.F.);
#1702=ORIENTED_EDGE('',*,*,#815,.F.);
#1703=DIRECTION('',(0.,1.,0.));
#1704=VECTOR('',#1703,1.);
#1705=CARTESIAN_POINT('',(144.010065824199,-31.5,-199.894560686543));
#1706=LINE('',#1705,#1704);
#1707=EDGE_CURVE('E478',#1698,#808,#1706,.T.);
#1708=ORIENTED_EDGE('',*,*,#1707,.F.);
#1709=EDGE_LOOP('',(#1700,#1701,#1702,#1708));
#1710=FACE_BOUND('',#1709,.T.);
#1711=ADVANCED_FACE('F1401',(#1710),#1692,.F.);
#1712=CARTESIAN_POINT('',(-152.5,-26.500761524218,0.0872620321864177));
#1713=DIRECTION('',(0.,-0.999847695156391,-0.0174524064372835));
#1714=DIRECTION('',(0.,0.0174524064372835,-0.999847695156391));
#1715=AXIS2_PLACEMENT_3D('',#1712,#1713,#1714);
#1716=PLANE('',#1715);
#1717=DIRECTION('',(0.,0.0174524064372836,-0.999847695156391));
#1718=VECTOR('',#1717,1.);
#1719=CARTESIAN_POINT('',(-94.8907450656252,-25.4678368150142,-59.0889549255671));
#1720=LINE('',#1719,#1718);
#1721=CARTESIAN_POINT('',(-94.8907450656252,-25.4678368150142,-59.0889549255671));
#1722=VERTEX_POINT('',#1721);
#1723=CARTESIAN_POINT('',(-94.8907450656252,-22.533118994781,-227.218826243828));
#1724=VERTEX_POINT('',#1723);
#1725=EDGE_CURVE('E679',#1722,#1724,#1720,.T.);
#1726=ORIENTED_EDGE('',*,*,#1725,.T.);
#1727=CARTESIAN_POINT('',(-76.2,-22.533118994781,-227.218826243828));
#1728=DIRECTION('',(0.,-0.999847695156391,-0.0174524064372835));
#1729=DIRECTION('',(0.,0.0174524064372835,-0.999847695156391));
#1730=AXIS2_PLACEMENT_3D('',#1727,#1728,#1729);
#1731=CIRCLE('',#1730,18.6907450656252);
#1732=CARTESIAN_POINT('',(-57.5092549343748,-22.533118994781,-227.218826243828));
#1733=VERTEX_POINT('',#1732);
#1734=EDGE_CURVE('E902',#1724,#1733,#1731,.T.);
#1735=ORIENTED_EDGE('',*,*,#1734,.T.);
#1736=DIRECTION('',(0.,-0.0174524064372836,0.999847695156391));
#1737=VECTOR('',#1736,1.);
#1738=CARTESIAN_POINT('',(-57.5092549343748,-25.4678368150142,-59.0889549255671));
#1739=LINE('',#1738,#1737);
#1740=CARTESIAN_POINT('',(-57.5092549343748,-25.4678368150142,-59.0889549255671));
#1741=VERTEX_POINT('',#1740);
#1742=EDGE_CURVE('E905',#1733,#1741,#1739,.T.);
#1743=ORIENTED_EDGE('',*,*,#1742,.T.);
#1744=CARTESIAN_POINT('',(-76.2,-25.4678368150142,-59.0889549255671));
#1745=DIRECTION('',(0.,-0.999847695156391,-0.0174524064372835));
#1746=DIRECTION('',(0.,0.0174524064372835,-0.999847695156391));
#1747=AXIS2_PLACEMENT_3D('',#1744,#1745,#1746);
#1748=CIRCLE('',#1747,18.6907450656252);
#1749=EDGE_CURVE('E907',#1741,#1722,#1748,.T.);
#1750=ORIENTED_EDGE('',*,*,#1749,.T.);
#1751=EDGE_LOOP('',(#1726,#1735,#1743,#1750));
#1752=FACE_BOUND('',#1751,.T.);
#1753=DIRECTION('',(0.,0.0174524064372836,-0.999847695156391));
#1754=VECTOR('',#1753,1.);
#1755=CARTESIAN_POINT('',(57.5092549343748,-25.4678368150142,-59.0889549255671));
#1756=LINE('',#1755,#1754);
#1757=CARTESIAN_POINT('',(57.5092549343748,-25.4678368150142,-59.0889549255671));
#1758=VERTEX_POINT('',#1757);
#1759=CARTESIAN_POINT('',(57.5092549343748,-22.533118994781,-227.218826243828));
#1760=VERTEX_POINT('',#1759);
#1761=EDGE_CURVE('E910',#1758,#1760,#1756,.T.);
#1762=ORIENTED_EDGE('',*,*,#1761,.T.);
#1763=CARTESIAN_POINT('',(76.2,-22.533118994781,-227.218826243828));
#1764=DIRECTION('',(0.,-0.999847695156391,-0.0174524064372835));
#1765=DIRECTION('',(0.,0.0174524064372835,-0.999847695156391));
#1766=AXIS2_PLACEMENT_3D('',#1763,#1764,#1765);
#1767=CIRCLE('',#1766,18.6907450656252);
#1768=CARTESIAN_POINT('',(94.8907450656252,-22.533118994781,-227.218826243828));
#1769=VERTEX_POINT('',#1768);
#1770=EDGE_CURVE('E913',#1760,#1769,#1767,.T.);
#1771=ORIENTED_EDGE('',*,*,#1770,.T.);
#1772=DIRECTION('',(0.,-0.0174524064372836,0.999847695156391));
#1773=VECTOR('',#1772,1.);
#1774=CARTESIAN_POINT('',(94.8907450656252,-25.4678368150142,-59.0889549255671));
#1775=LINE('',#1774,#1773);
#1776=CARTESIAN_POINT('',(94.8907450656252,-25.4678368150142,-59.0889549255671));
#1777=VERTEX_POINT('',#1776);
#1778=EDGE_CURVE('E916',#1769,#1777,#1775,.T.);
#1779=ORIENTED_EDGE('',*,*,#1778,.T.);
#1780=CARTESIAN_POINT('',(76.2,-25.4678368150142,-59.0889549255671));
#1781=DIRECTION('',(0.,-0.999847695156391,-0.0174524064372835));
#1782=DIRECTION('',(0.,0.0174524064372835,-0.999847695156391));
#1783=AXIS2_PLACEMENT_3D('',#1780,#1781,#1782);
#1784=CIRCLE('',#1783,18.6907450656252);
#1785=EDGE_CURVE('E918',#1777,#1758,#1784,.T.);
#1786=ORIENTED_EDGE('',*,*,#1785,.T.);
#1787=EDGE_LOOP('',(#1762,#1771,#1779,#1786));
#1788=FACE_BOUND('',#1787,.T.);
#1789=DIRECTION('',(0.,0.0174524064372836,-0.999847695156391));
#1790=VECTOR('',#1789,1.);
#1791=CARTESIAN_POINT('',(-18.6907450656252,-25.4678368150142,-59.0889549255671));
#1792=LINE('',#1791,#1790);
#1793=CARTESIAN_POINT('',(-18.6907450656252,-25.4678368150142,-59.0889549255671));
#1794=VERTEX_POINT('',#1793);
#1795=CARTESIAN_POINT('',(-18.6907450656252,-22.533118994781,-227.218826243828));
#1796=VERTEX_POINT('',#1795);
#1797=EDGE_CURVE('E921',#1794,#1796,#1792,.T.);
#1798=ORIENTED_EDGE('',*,*,#1797,.T.);
#1799=CARTESIAN_POINT('',(0.,-22.533118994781,-227.218826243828));
#1800=DIRECTION('',(0.,-0.999847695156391,-0.0174524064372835));
#1801=DIRECTION('',(0.,0.0174524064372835,-0.999847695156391));
#1802=AXIS2_PLACEMENT_3D('',#1799,#1800,#1801);
#1803=CIRCLE('',#1802,18.6907450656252);
#1804=CARTESIAN_POINT('',(18.6907450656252,-22.533118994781,-227.218826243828));
#1805=VERTEX_POINT('',#1804);
#1806=EDGE_CURVE('E924',#1796,#1805,#1803,.T.);
#1807=ORIENTED_EDGE('',*,*,#1806,.T.);
#1808=DIRECTION('',(0.,-0.0174524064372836,0.999847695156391));
#1809=VECTOR('',#1808,1.);
#1810=CARTESIAN_POINT('',(18.6907450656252,-25.4678368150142,-59.0889549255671));
#1811=LINE('',#1810,#1809);
#1812=CARTESIAN_POINT('',(18.6907450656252,-25.4678368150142,-59.0889549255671));
#1813=VERTEX_POINT('',#1812);
#1814=EDGE_CURVE('E927',#1805,#1813,#1811,.T.);
#1815=ORIENTED_EDGE('',*,*,#1814,.T.);
#1816=CARTESIAN_POINT('',(0.,-25.4678368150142,-59.0889549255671));
#1817=DIRECTION('',(0.,-0.999847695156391,-0.0174524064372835));
#1818=DIRECTION('',(0.,0.0174524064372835,-0.999847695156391));
#1819=AXIS2_PLACEMENT_3D('',#1816,#1817,#1818);
#1820=CIRCLE('',#1819,18.6907450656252);
#1821=EDGE_CURVE('E540',#1794,#1813,#1820,.F.);
#1822=ORIENTED_EDGE('',*,*,#1821,.F.);
#1823=EDGE_LOOP('',(#1798,#1807,#1815,#1822));
#1824=FACE_BOUND('',#1823,.T.);
#1825=ORIENTED_EDGE('',*,*,#1677,.T.);
#1826=ORIENTED_EDGE('',*,*,#368,.T.);
#1827=ORIENTED_EDGE('',*,*,#1699,.F.);
#1828=CARTESIAN_POINT('',(42.3455521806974,-23.041040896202,-198.12));
#1829=DIRECTION('',(0.,-0.999847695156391,-0.0174524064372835));
#1830=DIRECTION('',(0.,0.0174524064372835,-0.999847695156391));
#1831=AXIS2_PLACEMENT_3D('',#1828,#1829,#1830);
#1832=ELLIPSE('',#1831,101.695488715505,101.68);
#1833=CARTESIAN_POINT('',(42.3455521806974,-21.2662098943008,-299.8));
#1834=VERTEX_POINT('',#1833);
#1835=EDGE_CURVE('E473',#1834,#1698,#1832,.T.);
#1836=ORIENTED_EDGE('',*,*,#1835,.F.);
#1837=DIRECTION('',(1.,0.,0.));
#1838=VECTOR('',#1837,1.);
#1839=CARTESIAN_POINT('',(-152.5,-21.2662098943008,-299.8));
#1840=LINE('',#1839,#1838);
#1841=CARTESIAN_POINT('',(-42.3455521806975,-21.2662098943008,-299.8));
#1842=VERTEX_POINT('',#1841);
#1843=EDGE_CURVE('E454',#1842,#1834,#1840,.T.);
#1844=ORIENTED_EDGE('',*,*,#1843,.F.);
#1845=CARTESIAN_POINT('',(-42.3455521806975,-23.041040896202,-198.12));
#1846=DIRECTION('',(0.,-0.999847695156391,-0.0174524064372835));
#1847=DIRECTION('',(0.,-0.0174524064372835,0.999847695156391));
#1848=AXIS2_PLACEMENT_3D('',#1845,#1846,#1847);
#1849=ELLIPSE('',#1848,101.695488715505,101.68);
#1850=EDGE_CURVE('E472',#1676,#1842,#1849,.T.);
#1851=ORIENTED_EDGE('',*,*,#1850,.F.);
#1852=EDGE_LOOP('',(#1825,#1826,#1827,#1836,#1844,#1851));
#1853=FACE_BOUND('',#1852,.T.);
#1854=ADVANCED_FACE('F945',(#1752,#1788,#1824,#1853),#1716,.F.);
#1855=CARTESIAN_POINT('',(-152.5,31.5,-299.8));
#1856=DIRECTION('',(0.,0.,-1.));
#1857=DIRECTION('',(-1.,0.,0.));
#1858=AXIS2_PLACEMENT_3D('',#1855,#1856,#1857);
#1859=PLANE('',#1858);
#1860=ORIENTED_EDGE('',*,*,#1843,.T.);
#1861=DIRECTION('',(0.,1.,0.));
#1862=VECTOR('',#1861,1.);
#1863=CARTESIAN_POINT('',(42.3455521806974,31.5,-299.8));
#1864=LINE('',#1863,#1862);
#1865=EDGE_CURVE('E482',#799,#1834,#1864,.F.);
#1866=ORIENTED_EDGE('',*,*,#1865,.F.);
#1867=ORIENTED_EDGE('',*,*,#800,.T.);
#1868=DIRECTION('',(0.,1.,0.));
#1869=VECTOR('',#1868,1.);
#1870=CARTESIAN_POINT('',(-42.3455521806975,31.5,-299.8));
#1871=LINE('',#1870,#1869);
#1872=EDGE_CURVE('E484',#1842,#791,#1871,.T.);
#1873=ORIENTED_EDGE('',*,*,#1872,.F.);
#1874=EDGE_LOOP('',(#1860,#1866,#1867,#1873));
#1875=FACE_BOUND('',#1874,.T.);
#1876=ADVANCED_FACE('F946',(#1875),#1859,.F.);
#1877=CARTESIAN_POINT('',(-42.3455521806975,-31.5,-198.12));
#1878=DIRECTION('',(0.,-1.,0.));
#1879=DIRECTION('',(0.,0.,-1.));
#1880=AXIS2_PLACEMENT_3D('',#1877,#1878,#1879);
#1881=CYLINDRICAL_SURFACE('',#1880,101.68);
#1882=ORIENTED_EDGE('',*,*,#792,.T.);
#1883=ORIENTED_EDGE('',*,*,#1683,.T.);
#1884=ORIENTED_EDGE('',*,*,#1850,.T.);
#1885=ORIENTED_EDGE('',*,*,#1872,.T.);
#1886=EDGE_LOOP('',(#1882,#1883,#1884,#1885));
#1887=FACE_BOUND('',#1886,.T.);
#1888=ADVANCED_FACE('F943',(#1887),#1881,.F.);
#1889=CARTESIAN_POINT('',(42.3455521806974,-31.5,-198.12));
#1890=DIRECTION('',(0.,1.,0.));
#1891=DIRECTION('',(0.,0.,1.));
#1892=AXIS2_PLACEMENT_3D('',#1889,#1890,#1891);
#1893=CYLINDRICAL_SURFACE('',#1892,101.68);
#1894=ORIENTED_EDGE('',*,*,#1835,.T.);
#1895=ORIENTED_EDGE('',*,*,#1707,.T.);
#1896=ORIENTED_EDGE('',*,*,#809,.T.);
#1897=ORIENTED_EDGE('',*,*,#1865,.T.);
#1898=EDGE_LOOP('',(#1894,#1895,#1896,#1897));
#1899=FACE_BOUND('',#1898,.T.);
#1900=ADVANCED_FACE('F1366',(#1899),#1893,.F.);
#1901=CARTESIAN_POINT('',(0.,-21.6584170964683,-59.022461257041));
#1902=DIRECTION('',(0.,-0.999847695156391,-0.0174524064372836));
#1903=DIRECTION('',(0.,0.0174524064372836,-0.999847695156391));
#1904=AXIS2_PLACEMENT_3D('',#1901,#1902,#1903);
#1905=PLANE('',#1904);
#1906=CARTESIAN_POINT('',(0.,-18.7236992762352,-227.152332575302));
#1907=DIRECTION('',(0.,-0.999847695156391,-0.0174524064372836));
#1908=DIRECTION('',(0.,0.0174524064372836,-0.999847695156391));
#1909=AXIS2_PLACEMENT_3D('',#1906,#1907,#1908);
#1910=CIRCLE('',#1909,12.1379822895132);
#1911=CARTESIAN_POINT('',(-12.1379822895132,-18.7236992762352,-227.152332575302));
#1912=VERTEX_POINT('',#1911);
#1913=CARTESIAN_POINT('',(12.1379822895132,-18.7236992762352,-227.152332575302));
#1914=VERTEX_POINT('',#1913);
#1915=EDGE_CURVE('E496',#1912,#1914,#1910,.T.);
#1916=ORIENTED_EDGE('',*,*,#1915,.F.);
#1917=DIRECTION('',(0.,0.0174524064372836,-0.999847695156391));
#1918=VECTOR('',#1917,1.);
#1919=CARTESIAN_POINT('',(-12.1379822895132,-21.6584170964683,-59.022461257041));
#1920=LINE('',#1919,#1918);
#1921=CARTESIAN_POINT('',(-12.1379822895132,-21.6584170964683,-59.022461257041));
#1922=VERTEX_POINT('',#1921);
#1923=EDGE_CURVE('E494',#1922,#1912,#1920,.T.);
#1924=ORIENTED_EDGE('',*,*,#1923,.F.);
#1925=CARTESIAN_POINT('',(0.,-21.6584170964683,-59.022461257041));
#1926=DIRECTION('',(0.,-0.999847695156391,-0.0174524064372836));
#1927=DIRECTION('',(0.,0.0174524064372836,-0.999847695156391));
#1928=AXIS2_PLACEMENT_3D('',#1925,#1926,#1927);
#1929=CIRCLE('',#1928,12.1379822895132);
#1930=CARTESIAN_POINT('',(12.1379822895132,-21.6584170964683,-59.022461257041));
#1931=VERTEX_POINT('',#1930);
#1932=EDGE_CURVE('E497',#1931,#1922,#1929,.T.);
#1933=ORIENTED_EDGE('',*,*,#1932,.F.);
#1934=DIRECTION('',(0.,0.0174524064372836,-0.999847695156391));
#1935=VECTOR('',#1934,1.);
#1936=CARTESIAN_POINT('',(12.1379822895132,-21.6584170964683,-59.022461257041));
#1937=LINE('',#1936,#1935);
#1938=EDGE_CURVE('E499',#1914,#1931,#1937,.F.);
#1939=ORIENTED_EDGE('',*,*,#1938,.F.);
#1940=EDGE_LOOP('',(#1916,#1924,#1933,#1939));
#1941=FACE_BOUND('',#1940,.T.);
#1942=ADVANCED_FACE('F1356',(#1941),#1905,.F.);
#1943=CARTESIAN_POINT('',(76.2,-21.6584170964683,-59.022461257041));
#1944=DIRECTION('',(0.,-0.999847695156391,-0.0174524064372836));
#1945=DIRECTION('',(0.,0.0174524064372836,-0.999847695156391));
#1946=AXIS2_PLACEMENT_3D('',#1943,#1944,#1945);
#1947=PLANE('',#1946);
#1948=CARTESIAN_POINT('',(76.2,-18.7236992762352,-227.152332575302));
#1949=DIRECTION('',(0.,-0.999847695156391,-0.0174524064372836));
#1950=DIRECTION('',(0.,0.0174524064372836,-0.999847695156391));
#1951=AXIS2_PLACEMENT_3D('',#1948,#1949,#1950);
#1952=CIRCLE('',#1951,12.1379822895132);
#1953=CARTESIAN_POINT('',(64.0620177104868,-18.7236992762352,-227.152332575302));
#1954=VERTEX_POINT('',#1953);
#1955=CARTESIAN_POINT('',(88.3379822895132,-18.7236992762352,-227.152332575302));
#1956=VERTEX_POINT('',#1955);
#1957=EDGE_CURVE('E519',#1954,#1956,#1952,.T.);
#1958=ORIENTED_EDGE('',*,*,#1957,.F.);
#1959=DIRECTION('',(0.,0.0174524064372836,-0.999847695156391));
#1960=VECTOR('',#1959,1.);
#1961=CARTESIAN_POINT('',(64.0620177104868,-21.6584170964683,-59.022461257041));
#1962=LINE('',#1961,#1960);
#1963=CARTESIAN_POINT('',(64.0620177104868,-21.6584170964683,-59.022461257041));
#1964=VERTEX_POINT('',#1963);
#1965=EDGE_CURVE('E517',#1964,#1954,#1962,.T.);
#1966=ORIENTED_EDGE('',*,*,#1965,.F.);
#1967=CARTESIAN_POINT('',(76.2,-21.6584170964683,-59.022461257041));
#1968=DIRECTION('',(0.,-0.999847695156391,-0.0174524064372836));
#1969=DIRECTION('',(0.,0.0174524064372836,-0.999847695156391));
#1970=AXIS2_PLACEMENT_3D('',#1967,#1968,#1969);
#1971=CIRCLE('',#1970,12.1379822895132);
#1972=CARTESIAN_POINT('',(88.3379822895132,-21.6584170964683,-59.022461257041));
#1973=VERTEX_POINT('',#1972);
#1974=EDGE_CURVE('E480',#1973,#1964,#1971,.T.);
#1975=ORIENTED_EDGE('',*,*,#1974,.F.);
#1976=DIRECTION('',(0.,0.0174524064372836,-0.999847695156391));
#1977=VECTOR('',#1976,1.);
#1978=CARTESIAN_POINT('',(88.3379822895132,-21.6584170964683,-59.022461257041));
#1979=LINE('',#1978,#1977);
#1980=EDGE_CURVE('E505',#1956,#1973,#1979,.F.);
#1981=ORIENTED_EDGE('',*,*,#1980,.F.);
#1982=EDGE_LOOP('',(#1958,#1966,#1975,#1981));
#1983=FACE_BOUND('',#1982,.T.);
#1984=ADVANCED_FACE('F1346',(#1983),#1947,.F.);
#1985=CARTESIAN_POINT('',(-76.2,-21.6584170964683,-59.022461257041));
#1986=DIRECTION('',(0.,-0.999847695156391,-0.0174524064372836));
#1987=DIRECTION('',(0.,0.0174524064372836,-0.999847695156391));
#1988=AXIS2_PLACEMENT_3D('',#1985,#1986,#1987);
#1989=PLANE('',#1988);
#1990=CARTESIAN_POINT('',(-76.2,-18.7236992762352,-227.152332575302));
#1991=DIRECTION('',(0.,-0.999847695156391,-0.0174524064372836));
#1992=DIRECTION('',(0.,0.0174524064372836,-0.999847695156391));
#1993=AXIS2_PLACEMENT_3D('',#1990,#1991,#1992);
#1994=CIRCLE('',#1993,12.1379822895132);
#1995=CARTESIAN_POINT('',(-88.3379822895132,-18.7236992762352,-227.152332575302));
#1996=VERTEX_POINT('',#1995);
#1997=CARTESIAN_POINT('',(-64.0620177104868,-18.7236992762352,-227.152332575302));
#1998=VERTEX_POINT('',#1997);
#1999=EDGE_CURVE('E535',#1996,#1998,#1994,.T.);
#2000=ORIENTED_EDGE('',*,*,#1999,.F.);
#2001=DIRECTION('',(0.,0.0174524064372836,-0.999847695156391));
#2002=VECTOR('',#2001,1.);
#2003=CARTESIAN_POINT('',(-88.3379822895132,-21.6584170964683,-59.022461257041));
#2004=LINE('',#2003,#2002);
#2005=CARTESIAN_POINT('',(-88.3379822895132,-21.6584170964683,-59.022461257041));
#2006=VERTEX_POINT('',#2005);
#2007=EDGE_CURVE('E533',#2006,#1996,#2004,.T.);
#2008=ORIENTED_EDGE('',*,*,#2007,.F.);
#2009=CARTESIAN_POINT('',(-76.2,-21.6584170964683,-59.022461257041));
#2010=DIRECTION('',(0.,-0.999847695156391,-0.0174524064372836));
#2011=DIRECTION('',(0.,0.0174524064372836,-0.999847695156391));
#2012=AXIS2_PLACEMENT_3D('',#2009,#2010,#2011);
#2013=CIRCLE('',#2012,12.1379822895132);
#2014=CARTESIAN_POINT('',(-64.0620177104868,-21.6584170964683,-59.022461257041));
#2015=VERTEX_POINT('',#2014);
#2016=EDGE_CURVE('E502',#2015,#2006,#2013,.T.);
#2017=ORIENTED_EDGE('',*,*,#2016,.F.);
#2018=DIRECTION('',(0.,0.0174524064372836,-0.999847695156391));
#2019=VECTOR('',#2018,1.);
#2020=CARTESIAN_POINT('',(-64.0620177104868,-21.6584170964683,-59.022461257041));
#2021=LINE('',#2020,#2019);
#2022=EDGE_CURVE('E537',#1998,#2015,#2021,.F.);
#2023=ORIENTED_EDGE('',*,*,#2022,.F.);
#2024=EDGE_LOOP('',(#2000,#2008,#2017,#2023));
#2025=FACE_BOUND('',#2024,.T.);
#2026=ADVANCED_FACE('F1336',(#2025),#1989,.F.);
#2027=CARTESIAN_POINT('',(64.0620177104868,-29.1972687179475,-59.1540524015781));
#2028=DIRECTION('',(0.,0.0174524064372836,-0.999847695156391));
#2029=DIRECTION('',(0.,0.999847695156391,0.0174524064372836));
#2030=AXIS2_PLACEMENT_3D('',#2027,#2028,#2029);
#2031=CYLINDRICAL_SURFACE('',#2030,7.54);
#2032=CARTESIAN_POINT('',(64.0620177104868,-29.1972687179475,-59.1540524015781));
#2033=DIRECTION('',(0.,-0.0174524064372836,0.999847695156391));
#2034=DIRECTION('',(0.,-0.999847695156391,-0.0174524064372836));
#2035=AXIS2_PLACEMENT_3D('',#2032,#2033,#2034);
#2036=CIRCLE('',#2035,7.54);
#2037=EDGE_CURVE('E511',#1758,#1964,#2036,.F.);
#2038=ORIENTED_EDGE('',*,*,#2037,.T.);
#2039=ORIENTED_EDGE('',*,*,#1965,.T.);
#2040=CARTESIAN_POINT('',(64.0620177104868,-26.2625508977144,-227.283923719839));
#2041=DIRECTION('',(0.,-0.0174524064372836,0.999847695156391));
#2042=DIRECTION('',(0.,-0.999847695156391,-0.0174524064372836));
#2043=AXIS2_PLACEMENT_3D('',#2040,#2041,#2042);
#2044=CIRCLE('',#2043,7.54);
#2045=EDGE_CURVE('E513',#1954,#1760,#2044,.T.);
#2046=ORIENTED_EDGE('',*,*,#2045,.T.);
#2047=ORIENTED_EDGE('',*,*,#1761,.F.);
#2048=EDGE_LOOP('',(#2038,#2039,#2046,#2047));
#2049=FACE_BOUND('',#2048,.T.);
#2050=ADVANCED_FACE('F1326',(#2049),#2031,.T.);
#2051=CARTESIAN_POINT('',(76.2,-26.2625508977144,-227.283923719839));
#2052=DIRECTION('',(0.,-0.999847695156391,-0.0174524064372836));
#2053=DIRECTION('',(0.,0.0174524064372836,-0.999847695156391));
#2054=AXIS2_PLACEMENT_3D('',#2051,#2052,#2053);
#2055=TOROIDAL_SURFACE('',#2054,12.1379822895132,7.54);
#2056=ORIENTED_EDGE('',*,*,#2045,.F.);
#2057=ORIENTED_EDGE('',*,*,#1957,.T.);
#2058=CARTESIAN_POINT('',(88.3379822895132,-26.2625508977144,-227.283923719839));
#2059=DIRECTION('',(0.,-0.0174524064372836,0.999847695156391));
#2060=DIRECTION('',(0.,-0.999847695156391,-0.0174524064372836));
#2061=AXIS2_PLACEMENT_3D('',#2058,#2059,#2060);
#2062=CIRCLE('',#2061,7.54);
#2063=EDGE_CURVE('E514',#1956,#1769,#2062,.F.);
#2064=ORIENTED_EDGE('',*,*,#2063,.T.);
#2065=ORIENTED_EDGE('',*,*,#1770,.F.);
#2066=EDGE_LOOP('',(#2056,#2057,#2064,#2065));
#2067=FACE_BOUND('',#2066,.T.);
#2068=ADVANCED_FACE('F1316',(#2067),#2055,.T.);
#2069=CARTESIAN_POINT('',(76.2,-29.1972687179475,-59.1540524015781));
#2070=DIRECTION('',(0.,-0.999847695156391,-0.0174524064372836));
#2071=DIRECTION('',(0.,0.0174524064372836,-0.999847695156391));
#2072=AXIS2_PLACEMENT_3D('',#2069,#2070,#2071);
#2073=TOROIDAL_SURFACE('',#2072,12.1379822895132,7.54);
#2074=CARTESIAN_POINT('',(88.3379822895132,-29.1972687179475,-59.1540524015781));
#2075=DIRECTION('',(0.,-0.0174524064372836,0.999847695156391));
#2076=DIRECTION('',(0.,-0.999847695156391,-0.0174524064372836));
#2077=AXIS2_PLACEMENT_3D('',#2074,#2075,#2076);
#2078=CIRCLE('',#2077,7.54);
#2079=EDGE_CURVE('E493',#1777,#1973,#2078,.T.);
#2080=ORIENTED_EDGE('',*,*,#2079,.T.);
#2081=ORIENTED_EDGE('',*,*,#1974,.T.);
#2082=ORIENTED_EDGE('',*,*,#2037,.F.);
#2083=ORIENTED_EDGE('',*,*,#1785,.F.);
#2084=EDGE_LOOP('',(#2080,#2081,#2082,#2083));
#2085=FACE_BOUND('',#2084,.T.);
#2086=ADVANCED_FACE('F1306',(#2085),#2073,.T.);
#2087=CARTESIAN_POINT('',(88.3379822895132,-29.1972687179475,-59.1540524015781));
#2088=DIRECTION('',(0.,-0.0174524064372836,0.999847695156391));
#2089=DIRECTION('',(0.,-0.999847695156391,-0.0174524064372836));
#2090=AXIS2_PLACEMENT_3D('',#2087,#2088,#2089);
#2091=CYLINDRICAL_SURFACE('',#2090,7.54);
#2092=ORIENTED_EDGE('',*,*,#2063,.F.);
#2093=ORIENTED_EDGE('',*,*,#1980,.T.);
#2094=ORIENTED_EDGE('',*,*,#2079,.F.);
#2095=ORIENTED_EDGE('',*,*,#1778,.F.);
#2096=EDGE_LOOP('',(#2092,#2093,#2094,#2095));
#2097=FACE_BOUND('',#2096,.T.);
#2098=ADVANCED_FACE('F1296',(#2097),#2091,.T.);
#2099=CARTESIAN_POINT('',(-12.1379822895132,-29.1972687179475,-59.1540524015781));
#2100=DIRECTION('',(0.,0.0174524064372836,-0.999847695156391));
#2101=DIRECTION('',(0.,0.999847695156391,0.0174524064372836));
#2102=AXIS2_PLACEMENT_3D('',#2099,#2100,#2101);
#2103=CYLINDRICAL_SURFACE('',#2102,7.54);
#2104=CARTESIAN_POINT('',(-12.1379822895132,-29.1972687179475,-59.1540524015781));
#2105=DIRECTION('',(0.,-0.0174524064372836,0.999847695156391));
#2106=DIRECTION('',(0.,-0.999847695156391,-0.0174524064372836));
#2107=AXIS2_PLACEMENT_3D('',#2104,#2105,#2106);
#2108=CIRCLE('',#2107,7.54);
#2109=EDGE_CURVE('E487',#1794,#1922,#2108,.F.);
#2110=ORIENTED_EDGE('',*,*,#2109,.T.);
#2111=ORIENTED_EDGE('',*,*,#1923,.T.);
#2112=CARTESIAN_POINT('',(-12.1379822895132,-26.2625508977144,-227.283923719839));
#2113=DIRECTION('',(0.,-0.0174524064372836,0.999847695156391));
#2114=DIRECTION('',(0.,-0.999847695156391,-0.0174524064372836));
#2115=AXIS2_PLACEMENT_3D('',#2112,#2113,#2114);
#2116=CIRCLE('',#2115,7.54);
#2117=EDGE_CURVE('E489',#1912,#1796,#2116,.T.);
#2118=ORIENTED_EDGE('',*,*,#2117,.T.);
#2119=ORIENTED_EDGE('',*,*,#1797,.F.);
#2120=EDGE_LOOP('',(#2110,#2111,#2118,#2119));
#2121=FACE_BOUND('',#2120,.T.);
#2122=ADVANCED_FACE('F1286',(#2121),#2103,.T.);
#2123=CARTESIAN_POINT('',(0.,-26.2625508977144,-227.283923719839));
#2124=DIRECTION('',(0.,-0.999847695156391,-0.0174524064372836));
#2125=DIRECTION('',(0.,0.0174524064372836,-0.999847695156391));
#2126=AXIS2_PLACEMENT_3D('',#2123,#2124,#2125);
#2127=TOROIDAL_SURFACE('',#2126,12.1379822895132,7.54);
#2128=ORIENTED_EDGE('',*,*,#2117,.F.);
#2129=ORIENTED_EDGE('',*,*,#1915,.T.);
#2130=CARTESIAN_POINT('',(12.1379822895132,-26.2625508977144,-227.283923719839));
#2131=DIRECTION('',(0.,-0.0174524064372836,0.999847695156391));
#2132=DIRECTION('',(0.,-0.999847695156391,-0.0174524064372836));
#2133=AXIS2_PLACEMENT_3D('',#2130,#2131,#2132);
#2134=CIRCLE('',#2133,7.54);
#2135=EDGE_CURVE('E490',#1914,#1805,#2134,.F.);
#2136=ORIENTED_EDGE('',*,*,#2135,.T.);
#2137=ORIENTED_EDGE('',*,*,#1806,.F.);
#2138=EDGE_LOOP('',(#2128,#2129,#2136,#2137));
#2139=FACE_BOUND('',#2138,.T.);
#2140=ADVANCED_FACE('F1276',(#2139),#2127,.T.);
#2141=CARTESIAN_POINT('',(0.,-29.1972687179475,-59.1540524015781));
#2142=DIRECTION('',(0.,-0.999847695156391,-0.0174524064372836));
#2143=DIRECTION('',(0.,0.0174524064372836,-0.999847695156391));
#2144=AXIS2_PLACEMENT_3D('',#2141,#2142,#2143);
#2145=TOROIDAL_SURFACE('',#2144,12.1379822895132,7.54);
#2146=ORIENTED_EDGE('',*,*,#1821,.T.);
#2147=CARTESIAN_POINT('',(12.1379822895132,-29.1972687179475,-59.1540524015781));
#2148=DIRECTION('',(0.,-0.0174524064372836,0.999847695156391));
#2149=DIRECTION('',(0.,-0.999847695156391,-0.0174524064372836));
#2150=AXIS2_PLACEMENT_3D('',#2147,#2148,#2149);
#2151=CIRCLE('',#2150,7.54);
#2152=EDGE_CURVE('E508',#1813,#1931,#2151,.T.);
#2153=ORIENTED_EDGE('',*,*,#2152,.T.);
#2154=ORIENTED_EDGE('',*,*,#1932,.T.);
#2155=ORIENTED_EDGE('',*,*,#2109,.F.);
#2156=EDGE_LOOP('',(#2146,#2153,#2154,#2155));
#2157=FACE_BOUND('',#2156,.T.);
#2158=ADVANCED_FACE('F1266',(#2157),#2145,.T.);
#2159=CARTESIAN_POINT('',(12.1379822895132,-29.1972687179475,-59.1540524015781));
#2160=DIRECTION('',(0.,-0.0174524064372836,0.999847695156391));
#2161=DIRECTION('',(0.,-0.999847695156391,-0.0174524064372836));
#2162=AXIS2_PLACEMENT_3D('',#2159,#2160,#2161);
#2163=CYLINDRICAL_SURFACE('',#2162,7.54);
#2164=ORIENTED_EDGE('',*,*,#2135,.F.);
#2165=ORIENTED_EDGE('',*,*,#1938,.T.);
#2166=ORIENTED_EDGE('',*,*,#2152,.F.);
#2167=ORIENTED_EDGE('',*,*,#1814,.F.);
#2168=EDGE_LOOP('',(#2164,#2165,#2166,#2167));
#2169=FACE_BOUND('',#2168,.T.);
#2170=ADVANCED_FACE('F1256',(#2169),#2163,.T.);
#2171=CARTESIAN_POINT('',(-88.3379822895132,-29.1972687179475,-59.1540524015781));
#2172=DIRECTION('',(0.,0.0174524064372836,-0.999847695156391));
#2173=DIRECTION('',(0.,0.999847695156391,0.0174524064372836));
#2174=AXIS2_PLACEMENT_3D('',#2171,#2172,#2173);
#2175=CYLINDRICAL_SURFACE('',#2174,7.54);
#2176=CARTESIAN_POINT('',(-88.3379822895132,-29.1972687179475,-59.1540524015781));
#2177=DIRECTION('',(0.,-0.0174524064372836,0.999847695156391));
#2178=DIRECTION('',(0.,-0.999847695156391,-0.0174524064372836));
#2179=AXIS2_PLACEMENT_3D('',#2176,#2177,#2178);
#2180=CIRCLE('',#2179,7.54);
#2181=EDGE_CURVE('E528',#1722,#2006,#2180,.F.);
#2182=ORIENTED_EDGE('',*,*,#2181,.T.);
#2183=ORIENTED_EDGE('',*,*,#2007,.T.);
#2184=CARTESIAN_POINT('',(-88.3379822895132,-26.2625508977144,-227.283923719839));
#2185=DIRECTION('',(0.,-0.0174524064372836,0.999847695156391));
#2186=DIRECTION('',(0.,-0.999847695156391,-0.0174524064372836));
#2187=AXIS2_PLACEMENT_3D('',#2184,#2185,#2186);
#2188=CIRCLE('',#2187,7.54);
#2189=EDGE_CURVE('E510',#1996,#1724,#2188,.T.);
#2190=ORIENTED_EDGE('',*,*,#2189,.T.);
#2191=ORIENTED_EDGE('',*,*,#1725,.F.);
#2192=EDGE_LOOP('',(#2182,#2183,#2190,#2191));
#2193=FACE_BOUND('',#2192,.T.);
#2194=ADVANCED_FACE('F1246',(#2193),#2175,.T.);
#2195=CARTESIAN_POINT('',(-76.2,-26.2625508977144,-227.283923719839));
#2196=DIRECTION('',(0.,-0.999847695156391,-0.0174524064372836));
#2197=DIRECTION('',(0.,0.0174524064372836,-0.999847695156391));
#2198=AXIS2_PLACEMENT_3D('',#2195,#2196,#2197);
#2199=TOROIDAL_SURFACE('',#2198,12.1379822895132,7.54);
#2200=ORIENTED_EDGE('',*,*,#2189,.F.);
#2201=ORIENTED_EDGE('',*,*,#1999,.T.);
#2202=CARTESIAN_POINT('',(-64.0620177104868,-26.2625508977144,-227.283923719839));
#2203=DIRECTION('',(0.,-0.0174524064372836,0.999847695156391));
#2204=DIRECTION('',(0.,-0.999847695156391,-0.0174524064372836));
#2205=AXIS2_PLACEMENT_3D('',#2202,#2203,#2204);
#2206=CIRCLE('',#2205,7.54);
#2207=EDGE_CURVE('E530',#1998,#1733,#2206,.F.);
#2208=ORIENTED_EDGE('',*,*,#2207,.T.);
#2209=ORIENTED_EDGE('',*,*,#1734,.F.);
#2210=EDGE_LOOP('',(#2200,#2201,#2208,#2209));
#2211=FACE_BOUND('',#2210,.T.);
#2212=ADVANCED_FACE('F1238',(#2211),#2199,.T.);
#2213=CARTESIAN_POINT('',(-76.2,-29.1972687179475,-59.1540524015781));
#2214=DIRECTION('',(0.,-0.999847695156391,-0.0174524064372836));
#2215=DIRECTION('',(0.,0.0174524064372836,-0.999847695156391));
#2216=AXIS2_PLACEMENT_3D('',#2213,#2214,#2215);
#2217=TOROIDAL_SURFACE('',#2216,12.1379822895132,7.54);
#2218=CARTESIAN_POINT('',(-64.0620177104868,-29.1972687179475,-59.1540524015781));
#2219=DIRECTION('',(0.,-0.0174524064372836,0.999847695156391));
#2220=DIRECTION('',(0.,-0.999847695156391,-0.0174524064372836));
#2221=AXIS2_PLACEMENT_3D('',#2218,#2219,#2220);
#2222=CIRCLE('',#2221,7.54);
#2223=EDGE_CURVE('E544',#1741,#2015,#2222,.T.);
#2224=ORIENTED_EDGE('',*,*,#2223,.T.);
#2225=ORIENTED_EDGE('',*,*,#2016,.T.);
#2226=ORIENTED_EDGE('',*,*,#2181,.F.);
#2227=ORIENTED_EDGE('',*,*,#1749,.F.);
#2228=EDGE_LOOP('',(#2224,#2225,#2226,#2227));
#2229=FACE_BOUND('',#2228,.T.);
#2230=ADVANCED_FACE('F1228',(#2229),#2217,.T.);
#2231=CARTESIAN_POINT('',(-64.0620177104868,-29.1972687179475,-59.1540524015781));
#2232=DIRECTION('',(0.,-0.0174524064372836,0.999847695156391));
#2233=DIRECTION('',(0.,-0.999847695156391,-0.0174524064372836));
#2234=AXIS2_PLACEMENT_3D('',#2231,#2232,#2233);
#2235=CYLINDRICAL_SURFACE('',#2234,7.54);
#2236=ORIENTED_EDGE('',*,*,#2207,.F.);
#2237=ORIENTED_EDGE('',*,*,#2022,.T.);
#2238=ORIENTED_EDGE('',*,*,#2223,.F.);
#2239=ORIENTED_EDGE('',*,*,#1742,.F.);
#2240=EDGE_LOOP('',(#2236,#2237,#2238,#2239));
#2241=FACE_BOUND('',#2240,.T.);
#2242=ADVANCED_FACE('F1066',(#2241),#2235,.T.);
#2243=CARTESIAN_POINT('',(37.8080050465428,17.413098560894,-323.088));
#2244=DIRECTION('',(0.,-1.,0.));
#2245=DIRECTION('',(0.,0.,-1.));
#2246=AXIS2_PLACEMENT_3D('',#2243,#2244,#2245);
#2247=PLANE('',#2246);
#2248=ORIENTED_EDGE('',*,*,#221,.F.);
#2249=CARTESIAN_POINT('',(-11.5881176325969,17.413098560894,-295.148));
#2250=DIRECTION('',(0.,-1.,0.));
#2251=DIRECTION('',(0.,0.,-1.));
#2252=AXIS2_PLACEMENT_3D('',#2249,#2250,#2251);
#2253=CIRCLE('',#2252,27.94);
#2254=EDGE_CURVE('E643',#212,#98,#2253,.F.);
#2255=ORIENTED_EDGE('',*,*,#2254,.T.);
#2256=ORIENTED_EDGE('',*,*,#99,.T.);
#2257=CARTESIAN_POINT('',(11.5881176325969,17.413098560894,-295.148));
#2258=DIRECTION('',(0.,-1.,0.));
#2259=DIRECTION('',(0.,0.,-1.));
#2260=AXIS2_PLACEMENT_3D('',#2257,#2258,#2259);
#2261=CIRCLE('',#2260,27.94);
#2262=EDGE_CURVE('E52',#90,#234,#2261,.F.);
#2263=ORIENTED_EDGE('',*,*,#2262,.T.);
#2264=ORIENTED_EDGE('',*,*,#235,.F.);
#2265=EDGE_LOOP('',(#2248,#2255,#2256,#2263,#2264));
#2266=FACE_BOUND('',#2265,.T.);
#2267=ADVANCED_FACE('F1227',(#2266),#2247,.F.);
#2268=CARTESIAN_POINT('',(37.8080050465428,-17.413098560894,-323.088));
#2269=DIRECTION('',(0.,1.,0.));
#2270=DIRECTION('',(0.,0.,1.));
#2271=AXIS2_PLACEMENT_3D('',#2268,#2269,#2270);
#2272=PLANE('',#2271);
#2273=ORIENTED_EDGE('',*,*,#135,.T.);
#2274=CARTESIAN_POINT('',(-11.5881176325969,-17.413098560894,-295.148));
#2275=DIRECTION('',(0.,1.,0.));
#2276=DIRECTION('',(0.,0.,1.));
#2277=AXIS2_PLACEMENT_3D('',#2274,#2275,#2276);
#2278=CIRCLE('',#2277,27.94);
#2279=EDGE_CURVE('E654',#126,#316,#2278,.F.);
#2280=ORIENTED_EDGE('',*,*,#2279,.T.);
#2281=ORIENTED_EDGE('',*,*,#317,.F.);
#2282=ORIENTED_EDGE('',*,*,#345,.F.);
#2283=CARTESIAN_POINT('',(11.5881176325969,-17.413098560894,-295.148));
#2284=DIRECTION('',(0.,1.,0.));
#2285=DIRECTION('',(0.,0.,1.));
#2286=AXIS2_PLACEMENT_3D('',#2283,#2284,#2285);
#2287=CIRCLE('',#2286,27.94);
#2288=EDGE_CURVE('E656',#342,#134,#2287,.F.);
#2289=ORIENTED_EDGE('',*,*,#2288,.T.);
#2290=EDGE_LOOP('',(#2273,#2280,#2281,#2282,#2289));
#2291=FACE_BOUND('',#2290,.T.);
#2292=ADVANCED_FACE('F602',(#2291),#2272,.F.);
#2293=CARTESIAN_POINT('',(0.,0.,-330.2));
#2294=DIRECTION('',(0.,0.,1.));
#2295=DIRECTION('',(1.,0.,0.));
#2296=AXIS2_PLACEMENT_3D('',#2293,#2294,#2295);
#2297=CYLINDRICAL_SURFACE('',#2296,17.413098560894);
#2298=CARTESIAN_POINT('',(0.,0.,-330.2));
#2299=DIRECTION('',(0.,0.,-1.));
#2300=DIRECTION('',(-1.,0.,0.));
#2301=AXIS2_PLACEMENT_3D('',#2298,#2299,#2300);
#2302=CIRCLE('',#2301,17.413098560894);
#2303=CARTESIAN_POINT('',(-17.413098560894,0.,-330.2));
#2304=VERTEX_POINT('',#2303);
#2305=EDGE_CURVE('E579',#2304,#2304,#2302,.T.);
#2306=ORIENTED_EDGE('',*,*,#2305,.F.);
#2307=EDGE_LOOP('',(#2306));
#2308=FACE_BOUND('',#2307,.T.);
#2309=ORIENTED_EDGE('',*,*,#115,.T.);
#2310=ORIENTED_EDGE('',*,*,#173,.T.);
#2311=ORIENTED_EDGE('',*,*,#228,.T.);
#2312=ORIENTED_EDGE('',*,*,#244,.T.);
#2313=ORIENTED_EDGE('',*,*,#196,.T.);
#2314=ORIENTED_EDGE('',*,*,#75,.T.);
#2315=ORIENTED_EDGE('',*,*,#276,.T.);
#2316=ORIENTED_EDGE('',*,*,#347,.F.);
#2317=ORIENTED_EDGE('',*,*,#331,.F.);
#2318=ORIENTED_EDGE('',*,*,#299,.T.);
#2319=EDGE_LOOP('',(#2309,#2310,#2311,#2312,#2313,#2314,#2315,#2316,#2317,#2318));
#2320=FACE_BOUND('',#2319,.T.);
#2321=ADVANCED_FACE('F379',(#2308,#2320),#2297,.T.);
#2322=CARTESIAN_POINT('',(0.,0.,-330.2));
#2323=DIRECTION('',(0.,0.,-1.));
#2324=DIRECTION('',(-1.,0.,0.));
#2325=AXIS2_PLACEMENT_3D('',#2322,#2323,#2324);
#2326=PLANE('',#2325);
#2327=ORIENTED_EDGE('',*,*,#2305,.T.);
#2328=EDGE_LOOP('',(#2327));
#2329=FACE_BOUND('',#2328,.T.);
#2330=CARTESIAN_POINT('',(0.,0.,-330.2));
#2331=DIRECTION('',(0.,0.,-1.));
#2332=DIRECTION('',(-1.,0.,0.));
#2333=AXIS2_PLACEMENT_3D('',#2330,#2331,#2332);
#2334=CIRCLE('',#2333,13.1474560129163);
#2335=CARTESIAN_POINT('',(-13.1474560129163,0.,-330.2));
#2336=VERTEX_POINT('',#2335);
#2337=EDGE_CURVE('E391',#2336,#2336,#2334,.T.);
#2338=ORIENTED_EDGE('',*,*,#2337,.F.);
#2339=EDGE_LOOP('',(#2338));
#2340=FACE_BOUND('',#2339,.T.);
#2341=ADVANCED_FACE('F592',(#2329,#2340),#2326,.T.);
#2342=CARTESIAN_POINT('',(0.,0.,-330.2));
#2343=DIRECTION('',(0.,0.,1.));
#2344=DIRECTION('',(1.,0.,0.));
#2345=AXIS2_PLACEMENT_3D('',#2342,#2343,#2344);
#2346=CYLINDRICAL_SURFACE('',#2345,13.1474560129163);
#2347=ORIENTED_EDGE('',*,*,#2337,.T.);
#2348=EDGE_LOOP('',(#2347));
#2349=FACE_BOUND('',#2348,.T.);
#2350=CARTESIAN_POINT('',(0.,0.,-304.8));
#2351=DIRECTION('',(0.,0.,-1.));
#2352=DIRECTION('',(-1.,0.,0.));
#2353=AXIS2_PLACEMENT_3D('',#2350,#2351,#2352);
#2354=CIRCLE('',#2353,13.1474560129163);
#2355=CARTESIAN_POINT('',(-13.1474560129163,0.,-304.8));
#2356=VERTEX_POINT('',#2355);
#2357=EDGE_CURVE('E583',#2356,#2356,#2354,.T.);
#2358=ORIENTED_EDGE('',*,*,#2357,.F.);
#2359=EDGE_LOOP('',(#2358));
#2360=FACE_BOUND('',#2359,.T.);
#2361=ADVANCED_FACE('F589',(#2349,#2360),#2346,.F.);
#2362=ORIENTED_EDGE('',*,*,#2357,.T.);
#2363=EDGE_LOOP('',(#2362));
#2364=FACE_BOUND('',#2363,.T.);
#2365=ADVANCED_FACE('F600',(#2364),#23,.T.);
#2366=CARTESIAN_POINT('',(-11.5881176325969,-13.1474560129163,-295.148));
#2367=DIRECTION('',(0.,1.,0.));
#2368=DIRECTION('',(0.,0.,1.));
#2369=AXIS2_PLACEMENT_3D('',#2366,#2367,#2368);
#2370=CYLINDRICAL_SURFACE('',#2369,27.94);
#2371=ORIENTED_EDGE('',*,*,#2279,.F.);
#2372=ORIENTED_EDGE('',*,*,#127,.T.);
#2373=ORIENTED_EDGE('',*,*,#292,.F.);
#2374=ORIENTED_EDGE('',*,*,#323,.F.);
#2375=EDGE_LOOP('',(#2371,#2372,#2373,#2374));
#2376=FACE_BOUND('',#2375,.T.);
#2377=ADVANCED_FACE('F616',(#2376),#2370,.T.);
#2378=CARTESIAN_POINT('',(11.5881176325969,-13.1474560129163,-295.148));
#2379=DIRECTION('',(0.,-1.,0.));
#2380=DIRECTION('',(0.,0.,-1.));
#2381=AXIS2_PLACEMENT_3D('',#2378,#2379,#2380);
#2382=CYLINDRICAL_SURFACE('',#2381,27.94);
#2383=ORIENTED_EDGE('',*,*,#262,.F.);
#2384=ORIENTED_EDGE('',*,*,#141,.T.);
#2385=ORIENTED_EDGE('',*,*,#2288,.F.);
#2386=ORIENTED_EDGE('',*,*,#343,.F.);
#2387=EDGE_LOOP('',(#2383,#2384,#2385,#2386));
#2388=FACE_BOUND('',#2387,.T.);
#2389=ADVANCED_FACE('F621',(#2388),#2382,.T.);
#2390=CARTESIAN_POINT('',(-11.5881176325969,13.1474560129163,-295.148));
#2391=DIRECTION('',(0.,1.,0.));
#2392=DIRECTION('',(-1.,0.,0.));
#2393=AXIS2_PLACEMENT_3D('',#2390,#2391,#2392);
#2394=CYLINDRICAL_SURFACE('',#2393,27.94);
#2395=ORIENTED_EDGE('',*,*,#159,.F.);
#2396=ORIENTED_EDGE('',*,*,#107,.T.);
#2397=ORIENTED_EDGE('',*,*,#2254,.F.);
#2398=ORIENTED_EDGE('',*,*,#213,.F.);
#2399=EDGE_LOOP('',(#2395,#2396,#2397,#2398));
#2400=FACE_BOUND('',#2399,.T.);
#2401=ADVANCED_FACE('F628',(#2400),#2394,.T.);
#2402=CARTESIAN_POINT('',(11.5881176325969,13.1474560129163,-295.148));
#2403=DIRECTION('',(0.,-1.,0.));
#2404=DIRECTION('',(0.,0.,-1.));
#2405=AXIS2_PLACEMENT_3D('',#2402,#2403,#2404);
#2406=CYLINDRICAL_SURFACE('',#2405,27.94);
#2407=ORIENTED_EDGE('',*,*,#2262,.F.);
#2408=ORIENTED_EDGE('',*,*,#91,.T.);
#2409=ORIENTED_EDGE('',*,*,#189,.F.);
#2410=ORIENTED_EDGE('',*,*,#241,.F.);
#2411=EDGE_LOOP('',(#2407,#2408,#2409,#2410));
#2412=FACE_BOUND('',#2411,.T.);
#2413=ADVANCED_FACE('F33',(#2412),#2406,.T.);
#2414=CLOSED_SHELL('',(#145,#177,#200,#232,#248,#280,#303,#335,#351,#740,#771,#845,#869,#1003,
#1015,#1027,#1059,#1083,#1108,#1125,#1167,#1199,#1223,#1248,#1265,#1307,#1339,#1363,#1388,#1405,
#1447,#1471,#1489,#1507,#1519,#1543,#1561,#1579,#1591,#1615,#1633,#1651,#1663,#1687,#1711,#1854,
#1876,#1888,#1900,#1942,#1984,#2026,#2050,#2068,#2086,#2098,#2122,#2140,#2158,#2170,#2194,#2212,
#2230,#2242,#2267,#2292,#2321,#2341,#2361,#2365,#2377,#2389,#2401,#2413));
#2415=MANIFOLD_SOLID_BREP('B2',#2414);
#2416=ADVANCED_BREP_SHAPE_REPRESENTATION('',(#18,#2415),#14);
#2417=SHAPE_DEFINITION_REPRESENTATION(#9,#2416);
ENDSEC;
END-ISO-10303-21;
